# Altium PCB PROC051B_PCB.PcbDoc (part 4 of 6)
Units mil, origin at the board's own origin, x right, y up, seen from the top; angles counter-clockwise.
Board outline 3304.03 x 2647.77 mil, 6 copper layers (TOP, L2, L3, L4, L5, BOTTOM), stack 55.54 mil thick; 356 components, 272 nets, 1247 pads, 1391 vias.

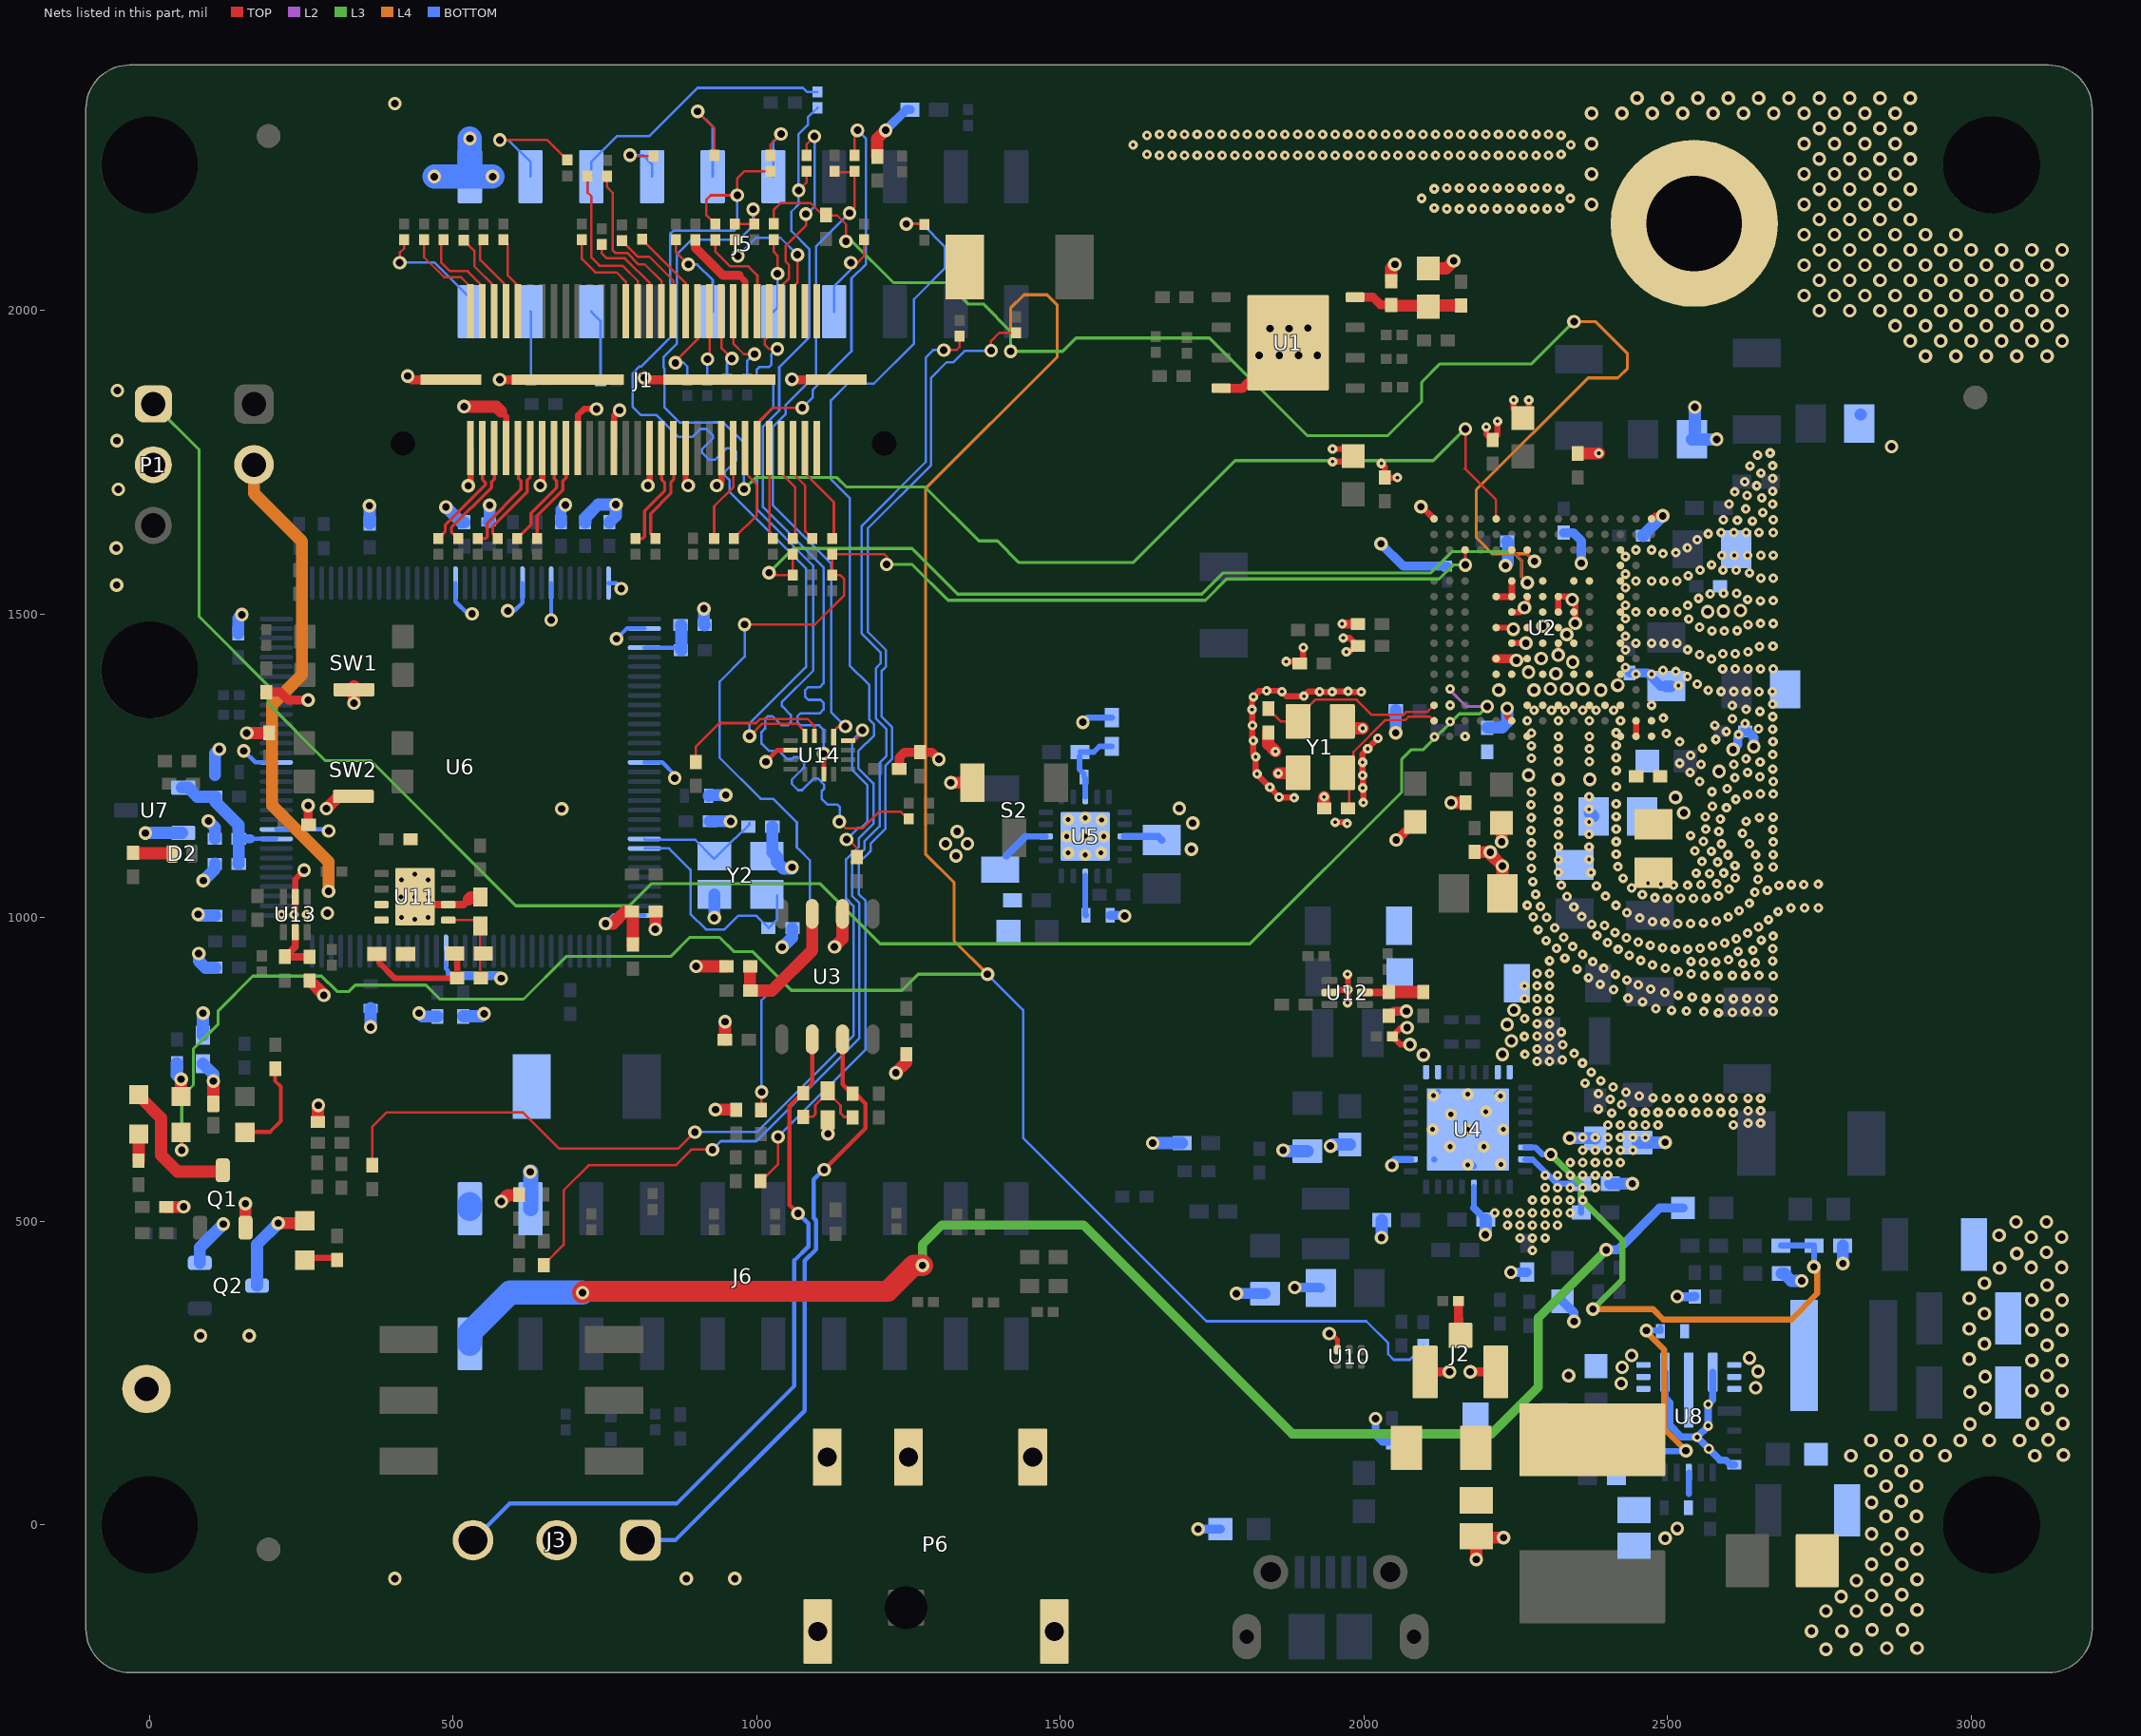
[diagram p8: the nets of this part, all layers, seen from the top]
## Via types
v1: diameter 22.4, hole 12.2, TOP to BOTTOM, tented both sides, 729 vias
v2: diameter 13.77/15.74 (per signal layer), hole 5.9, TOP to L2, tented both sides, 620 vias
v3: diameter 19.68, hole 7.87, TOP to BOTTOM, 25 vias
v4: diameter 22.4, hole 12.1, TOP to BOTTOM, tented both sides, 7 vias
v5: diameter 19.68, hole 7.87, TOP to BOTTOM, tented both sides, 5 vias
v6: diameter 16, hole 8, TOP to BOTTOM, tented both sides, 4 vias
v7: diameter 22.4/22.4/22.4/22.4/22.4/22.4 (per signal layer), hole 12.2, TOP to BOTTOM, tented both sides, 1 vias

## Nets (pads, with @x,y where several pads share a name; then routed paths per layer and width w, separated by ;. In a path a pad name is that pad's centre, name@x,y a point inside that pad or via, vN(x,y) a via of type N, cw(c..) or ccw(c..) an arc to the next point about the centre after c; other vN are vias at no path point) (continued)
AR_TDI: R29.1 R30.1 U2.R11 | length 2240.1
  TOP w4: R29.1@963.83,2142.71 R30.1@995.75,2142.71 995.75,2167 995.75,2168.25 994.5,2167 v1(994,2167) ; v1(2167.14,1804.93) 2167.14,1741.14 2166,1740 2217.78,1688.22 U2.R11@2217.78,1657.03
  L3 w5: v1(979,1706) 998,1725 1132.14,1725 1147.6,1709.54 1277.06,1709.54 1365.9,1620.7 1396.3,1620.7 1432,1585 1619.86,1585 1787.86,1753 2114,1753 2165.93,1804.93 v1(2167.14,1804.93)
  BOTTOM w4: v1(979,1706) 979,1782 945,1816 928.35,1816 927.65,1815.3 873.55,1815.3 848.3,1840.55 848.3,1904.55 846.8,1906.05 846.8,1923.8 868.2,1945.2 868.2,2092.2 893,2117 971.23,2117 994,2139.77 v1(994,2167)
AR_TDO_SOP0: R67.2 R71.1 R89.1 U2.N13 | length 2324.2
  TOP w4: v1(980,1483) 980.2,1482.8 1025.12,1482.8 1025.32,1483 1096,1483 1144,1531 1144,1558 1137.29,1564.71 R71.1@1124.33,1564.71 1124.25,1564.79 R67.2@1124.25,1598.73 1210.27,1598.73 1214,1595 v1(1214,1582) ; R89.1@1006.58,682.45 R89.1@1006.58,683.24 1008,684.66 v1(1008,713) ; U2.N13@2166.6,1605.85 2167,1606.25 2167,1605.85 v1(2167,1581)
  L3 w5: v1(1214,1582) 1256,1582 1315,1523 1739,1523 1774,1558 2124,1558 2147,1581 v1(2167,1581)
  BOTTOM w4: v1(980,1483) 980,1430 938.8,1388.8 938.8,1263.62 1006.42,1196 1027.14,1196 1066,1157.14 1066,1115.86 1069.66,1112.2 1070.09,1112.2 1087.5,1094.8 1087.5,943.5 1008,864 v1(1008,713)
AR_TMS: R65.2 R69.1 U2.N10 | length 1501.2
  TOP w4: v1(1020.36,1568.35) 1024,1564.71 R69.1@1059.25,1564.71 R65.2@1059.25,1598.73 ; U2.N10@2243.37,1605.85 2260,1589.22 2260,1561 v1(2269,1552)
  L3 w5: v1(1020.36,1568.35) 1060.11,1608.1 1255.7,1608.1 1330.8,1533 1733,1533 1768,1568 2110,1568 2145.3,1603.3 2244.56,1603.3 2259.7,1588.16 2259.7,1561.3 v1(2269,1552)
AR_VBGAP: C56.2 U2.B10 | length 82.6
  TOP w10: v1(2236,1345) 2236,1331.73 U2.B10@2243.37,1324.36
  BOTTOM w20: C56.2@2203.69,1313.3 2227.3,1313.3 2236,1322 v1(2236,1345)
AR_VOUT_PA: C10.2 C65.2 C83.2 R137.2 U2.A2 U2.B2 | length 25.6
  TOP w10: U2.A2@2448.09,1298.77 U2.B2@2448.09,1324.36
  other v1: 2526.79,1172.71 2513.12,1198
AR_VSENSE: P1.1 U2.D14 | length 3040.6
  L2 w5: v2@2141.01,1375.54 2168.54,1348 v1(2203,1348)
  L3 w5: P1.1@6.27,1846.15 81.5,1770.92 81.5,1496 195.2,1382.3 195.2,1352.8 289,1259 364,1259 603.2,1019.8 790.3,1019.8 826.7,1056.2 1104,1056.2 1203.2,957 1812.14,957 2062.3,1207.16 2062.3,1261.3 2078,1277 2098,1277 2157,1336 2191,1336 v1(2203,1348)
  other v2: 2142,1377
AR_WARMRST: DS2.2 R15.1 R18.1 R149.2 U2.N9 | length 6560
  TOP w4: DS2.2@52,647.46 DS2.2@52,646.47 52,618 v1(53,617) ; R18.1@1028.21,2143.06 1028.21,2166.22 1038.99,2177 1089.07,2177 1111.26,2154.8 R15.1@1114,2157.53 1114,2156.75 1132.24,2156.75 1147,2141.99 v1(1147,2114) ; U2.N9@2268.96,1605.85 2268.96,1599.04 v1(2281,1587)
  L3 w5: v1(53,617) 53,705.23 72.16,724.39 72.16,784.16 113,825 113,847 170,904 283.26,904 308.65,878.61 328.4,878.61 338.79,889 455,889 478,866 616,866 686.22,936.22 858.1,936.22 889.58,967.7 938.89,967.7 962.29,944.3 992.7,944.3 1056.7,880.3 1239.3,880.3 1266,907 v1(1380,907) ; v1(1147,2114) 1157,2114 1225,2046 1313,2046 1348,2011 1373,2011 1418,1966 v1(1418,1933) 1504,1933 1526,1955 1745.9,1955 1906.9,1794 2039,1794 2095,1850 2095,1881.86 2125.44,1912.3 2276.3,1912.3 v1(2346,1982)
  L4 w5: v1(1380,907) 1325,962 1325,1058 1277.98,1105.02 1277.98,1706.98 1495,1924 1495,2009 1478,2026 1440,2026 1418,2004 v1(1418,1933) ; v1(2281,1587) 2268.3,1599.7 2211.3,1599.7 2185,1626 2185,1705 2369,1889 2418.26,1889 2434.06,1904.81 2434.06,1929.34 2381.7,1981.7 2346,1981.7 2341.7,1981.7 2342,1982 v1(2346,1982)
  BOTTOM w4: v1(1380,907) 1438.7,848.3 1438.7,637.3 1740.61,335.39 2003.85,335.39 2040,299.23 2040,281 2049,272 2075.69,272 R149.2@2098,294.31
AR_XTALM: C9.2 U2.C15 Y1.1 | length 318.1
  TOP w4: C9.2@1842.36,1344.03 1862.93,1323.46 1891.58,1323.46 1892.3,1323.46 1892.3,1331.6 1919.8,1359.1 1987.9,1359.1 2013,1334 2065,1334 2070.2,1339.2 2104.67,1339.2 U2.C15@2115.42,1349.95
AR_XTALP: C15.2 U2.B15 Y1.3 | length 264
  TOP w4: C15.2@1975.7,1180.4 1975.53,1180.57 1975.53,1228.43 1965.14,1238.82 1982.7,1256.38 1982.7,1273.22 2035.48,1326 2068.31,1326 2073.51,1331.2 2108.57,1331.2 U2.B15@2115.42,1324.36
CAN_RX: R12.1 U14.3 | length 260.6
  TOP w4: R12.1@900,1256.68 900,1282 938.59,1320.59 998.85,1320.59 1005.76,1327.5 1083.63,1327.5 1095.13,1316 U14.3@1095.13,1299.5
CAN_TX: R11.1 U14.16 | length 286.9
  TOP w4: v1(1148,1129) 1151,1129 1165,1115 R11.1@1165,1099.68 ; U14.16@1150.24,1291.62 1161.62,1291.62 1174,1304 v1(1174,1309)
  BOTTOM w4: v1(1148,1129) 1166.8,1147.8 1171.8,1147.8 1182.54,1158.54 1182.54,1218.04 1157,1243.58 1157,1292 v1(1174,1309)
CS1: R1.2 R17.1 U14.11 | length 1358.5
  TOP w4: v1(1069,2198) 1082,2211 R17.1@1082,2229.73
  TOP w8: v1(1110,1270) 1110.87,1269.13 U14.11@1110.87,1236.5
  BOTTOM w4: R1.2@1100,2334.01 1084.08,2318.08 1084.08,2305.8 1069,2290.72 v1(1069,2198) 1069,2175 1057,2163 1057,2131 1087,2101 1087,1957 1037,1907 1037,1835.7 1010.3,1809.01 1010.3,1676.7 1110,1577 1110,1386 1104,1380 1085,1380 1080,1375 1080,1364 1085,1359 1105,1359 1110,1354 1110,1343 1104,1337 1072,1337 1067,1332 1067,1322 1072,1317 1103,1317 1110,1310 v1(1110,1270)
D_LOGGER: J5.4 R60.1 | length 214.1
  TOP w4: v1(577,2281) 654.99,2281 R60.1@688,2247.99
  BOTTOM w4: v1(577,2281) 591,2281 627.5,2244.5 J5.4@627.5,2220.72
GND: C1.1 C2.1 C3.1 C4.1 C5.1 C6.1 C7.1 C8.2 C9.1 C10.1 C11.1 C12.1 C13.1 C14.1 C15.1 C16.1 C17.1 C20.1 C21.2 C22.2 C23.2 C24.1 C25.2 C26.2 C27.2 C28.2 C29.2 C30.2 C31.2 C32.2 C33.1 C34.2 C35.2 C36.1 C38.2 C39.1 C41.2 C42.1 C43.1 C44.2 C45.1 C46.2 C47.1 C48.1 C49.1 C50.1 C51.1 C52.1 C53.1 C54.1 C56.1 C57.1 C58.1 C59.2 C60.2 C61.2 C62.2 C63.1 C64.1 C65.1 C66.1 C67.1 C68.2 C69.1 C70.1 C71.1 C73.2 C74.1 C75.1 C76.2 C77.2 C78.2 C79.2 C81.2 C82.2 C83.1 C84.1 C85.2 C86.1 C87.1 C89.1 C90.1 C91.1 C92.1 C93.2 C94.1 C97.1 C98.2 C101.2 C103.2 C104.2 J1.18 J1.24 J1.30 J1.36 J1.42 J1.48 J1.54 J1.60 J1.MP1 J1.MP2 J1.MP3 J1.MP4 J2.2 J2.3 J3.2 J5.2 J6.4 P1.2 P6.2 P6.3 P6.4 P6.5 pad.1 Q1.2 Q2.2 R13.1 R73.1 R79.1 R86.2 R88.1 R96.1 R110.1 R114.1 R118.1 R123.2 R125.1 R126.2 R138.1 R139.1 R145.1 R147.2 R153.1 R158.2 R167.1 R174.1 R175.1 R190.1 R193.1 R208.2 S2.3 SW1.5 SW2.5 TP1.1 U1.4 U1.9 U2.A1 U2.A3 U2.A5 U2.A7 U2.A9 U2.A13 U2.A15 U2.B1 U2.B3 U2.B5 U2.B7 U2.B9 U2.B14 U2.C1 U2.C3 U2.C4 U2.C5 U2.C6 U2.C7 U2.C8 U2.C9 U2.C14 U2.E1 U2.E2 U2.E3 U2.E5 U2.E6 U2.E8 U2.E10 U2.E11 U2.F3 U2.F9 U2.F11 U2.G1 U2.G2 U2.G3 U2.G6 U2.G7 U2.G8 U2.G10 U2.H3 U2.H7 U2.H9 U2.H11 U2.J1 U2.J2 U2.J3 U2.J6 U2.J7 U2.J8 U2.J10 U2.K3 U2.K7 U2.K8 U2.K9 U2.K10 U2.K11 U2.L1 U2.L2 U2.L3 U2.L5 U2.L6 U2.L8 U2.L10 U2.M3 U2.N1 U2.N2 U2.N3 U2.R1 U2.R15 U3.2 U4.4 U4.10 U4.17 U4.18 U4.23 U4.24 U4.33 U5.8 U5.18 U5.21 U6.10 U6.17 U6.48 U6.55 U6.58 U6.64 U6.66 U6.80 U6.114 U7.2 U8.3 U8.5 U8.6 U8.7 U8.8 U8.10 U8.11 U8.12 U8.13 U8.17 U8.20 U10.3 U11.6 U11.9@436.9,1034.5 U12.2 U13.2 U14.6 Y1.2 Y1.4 Y2.2 Y2.4 | length 8165.6
  TOP w7: U2.J7@2318.89,1503.49 U2.J7@2320.14,1503.49 U2.J7@2320.61,1503.49 ; v1@2320.14,1432.71 U2.G7@2320.14,1452.31
  TOP w7.5: v1(1015,1257) 1033.87,1275.87 U14.6@1055.76,1275.87
  TOP w8: v1(1943,315) 1943,318 1944.5,316.5 1956.32,304.68 U10.3@1956.32,288.57
  TOP w9: v1@2268.96,1515.31 U2.K9@2268.96,1529.08
  TOP w10: v2@240,1013 U13.2@240,1034.53 240,1063.8 v1(254.6,1078.4) ; v1(524.98,1711.53) 528.62,1715.17 J1.60@528.62,1773.27 ; 579,1834 587.67,1825.33 587.67,1773.46 J1.54@587.67,1773.27 ; v1(643.53,1711.97) 646.73,1715.17 J1.48@646.73,1773.27 ; J1.42@705.78,1773.27 705.78,1773.46 705.78,1828 715.78,1838 v1(736,1838) ; J1.36@764.84,1773.27 764.84,1773.46 764.84,1826.84 v1(774,1836) ; v1(820.61,1711.89) 823.89,1715.17 J1.30@823.89,1773.27 ; J1.24@882.95,1773.27 882.95,1716.05 v1(887,1712) ; v1(934,1712) 938.83,1712 942,1715.17 J1.18@942,1773.27 ; v2(1872,1422) 1894.32,1422 1895.7,1422 1900,1426.3 v2(1900,1445) ; v2(1885,1197.5) 1885,1198.4 v2(1860.1,1198.4) 1860.1,1199.9 v2(1845,1215) 1824,1236 v2(1824,1237) 1821.6,1239.4 v2(1821.6,1265) 1817.7,1268.9 v2(1817.7,1291.5) 1816.3,1292.9 v2(1816.3,1316.6) 1816.3,1342.3 v2(1815.7,1342.9) 1815.7,1361.7 v2(1818,1364) 1827.9,1373.9 v2(1839.7,1373.9) 1863.6,1373.9 v2(1865,1372.5) 1872.6,1364.9 v2(1901.3,1364.9) 1908.8,1372.4 v2(1927,1372.4) 1927.4,1372 v2(1947.6,1372) 1948.43,1372.83 v2(1974.02,1372.83) 1974.95,1371.9 1995.7,1371.9 v2(1995.8,1372) ; U12.2@1943.37,876.9 1953.7,876.9 1958.3,881.5 v2(1973.69,881.5) ; v2(1948.3,1751.3) 1973,1751.3 C89.1@1982.1,1760.4 1970.4,1772.1 v2(1948.3,1772.1) ; v2(1952.62,1157.3) 1970.3,1157.3 v2(1972.4,1155.2) ; v2(1966,1461) 1976,1461 1989.66,1447.34 1986.31,1444 1982,1444 1976,1438 v2(1971,1438) ; v2(1973,859.98) 1973.69,860.66 v2(1973.69,881.5) ; v2(1973,907) 1973.69,906.31 v2(1973.69,881.5) ; v2(1999.1,1189.7) 1999.1,1212.8 v2(1998.1,1213.8) 1998.1,1234 v2(1997.7,1234.4) v2(1997.7,1256.1) 1997.7,1270 v2(2006.2,1278.5) v2(2023.15,1295.45) ; v2(2028.8,1748.3) 2034.5,1742.6 C6.1@2034.5,1725.28 2034.5,1724.9 v2(2055.3,1724.9) ; v1(2071,819) 2060.99,819 R167.1@2046.59,804.6 2060.19,791 v1(2076,791) ; v1(2094,1677) 2095.45,1677 U2.R15@2115.42,1657.03 ; v2(2201.4,1808.4) 2201.4,1796.9 2211.4,1786.9 2211.95,1786.9 2212.14,1787.09 2219.9,1794.85 v2(2219.9,1817.8) ; U2.H11@2217.78,1477.9 2246,1477.9 2248.55,1477.9 v1(2246,1475.35) v1@2246,1472 ; U2.G10@2243.37,1452.31 v1@2266.94,1452.31 ; U2.J10@2243.37,1503.49 2257.14,1503.49 v1(2264.45,1510.8) ; v2(2246.6,1852.7) 2246.6,1837.55 2261.25,1822.9 C87.1@2261.8,1822.9 2271.5,1832.6 v2(2271.5,1852.5) ; U2.J7@2320.14,1503.49 U2.K7@2320.14,1529.08 2336.12,1529.08 2342.1,1523.1 2348,1517.2 2348,1503.49 v1(2348,1485) ; U2.R1@2473.68,1657.03 2478.65,1662 v1(2492,1662)
  TOP w11: U2.K11@2217.78,1529.08 U2.K10@2243.37,1529.08 U2.L10@2243.37,1554.67
  TOP w12: v5(436.9,1034.5) 449.7,1021.7 459.54,1021.7 U11.6@492.02,1021.7 516.9,1021.7 525.7,1030.5
  TOP w15: R73.1@192.05,1372.02 214.98,1372.02 228.5,1358.5 v1(261,1358.5) ; R79.1@261.15,1153.14 v1(261.15,1185) ; v1(425.2,1892.3) 431.24,1886.26 J1.MP4@496.12,1886.26 J1.MP4@496.73,1886.26 ; v1(576.76,1886.26) J1.MP3@688.64,1886.26 J1.MP3@689.25,1886.26 ; v1(815,1889) 817.74,1886.26 J1.MP2@938.64,1886.26 J1.MP2@939.25,1886.26 ; v1(1058,1887) 1058.74,1886.26 J1.MP1@1131.16,1886.26 J1.MP1@1131.77,1886.26 ; C97.1@1234.68,1245 1235,1245.32 1235,1264 1243.69,1272.69 R208.2@1269,1272.69 1288.31,1272.69 v1(1300,1261) ; U1.4@1762.93,1872.18 U1.4@1764.89,1872.18 1800.13,1872.18 1857.42,1929.47 U1.9@1875.13,1947.18 ; v2(1964,1484) C4.1@1990.32,1484 ; C91.1@2041,838.32 2041.32,838 2049.32,846 v1(2070,846) ; v1(2053,1128) 2054.55,1128 C14.1@2084.45,1157.9 ; J2.2@2100.93,252 v1(2141,252) ; v1(2175,252) J2.3@2217.07,252 ; U2.F11@2217.78,1426.72 2248.28,1426.72 v1(2251,1424)
  TOP w20: R110.1@26.62,523.77 R110.1@27.4,523.77 v1@55,523.77 ; Q1.2@157.98,489.51 v1(158,529) ; v1(160,1304.2) C11.1@197.3,1304.2 ; C92.1@263.6,896.9 263.79,896.71 287.1,873.4 v1(287.1,872.3) ; R114.1@277.32,664 277.32,690.32 v1(278,691) ; v1(291.2,1179.7) 311.4,1199.9 SW2.5@335.7,1199.9 ; v1(336.65,1353.5) SW1.5@336.65,1375.52 SW1.5@336.65,1381.42 ; v1(518,1842) 571,1842 579,1834 ; 525.7,1030.5 529.11,1033.91 R193.1@544.7,1033.94 R193.1@544.9,1033.91 ; v1(579.2,532.5) 589.85,543.15 R96.1@608.78,543.15 ; v1(833,981) 833.3,981.3 C71.1@833.3,1010.5 ; v1(900,920) C16.1@949.91,920 C16.1@950.3,920 ; v1(932,684) 964.87,684 965.73,683.14 R88.1@966.12,682.75 ; C20.1@947.89,798.85 v1(947.89,828.89) ; v1(1117.1,644.1) C24.1@1117.1,667.48 C24.1@1117.1,671.8 ; v1(1128,952) 1141.31,965.31 U3.2@1141.31,1006.33 U3.2@1141.31,1007.31 ; R13.1@1198.4,2252.95 R13.1@1198.4,2253.73 1198.4,2283 v1(1212.4,2297) ; v1(1229,744.5) 1246.3,761.8 R86.2@1246.3,775.01 R86.2@1246.3,775.8 ; v1(1319.72,1222.28) S2.3@1355.1,1222.28 ; C9.1@1842.36,1305.43 C9.1@1842.36,1305.05 1842.36,1285.94 v2(1854.3,1274) ; v2(1859,1238) 1891.48,1238 1891.87,1238.39 Y1.2@1892.3,1238.82 ; C15.1@1934.32,1180.4 v2(1934.32,1198.99) ; Y1.4@1965.14,1323.46 1976.6,1312 v2(1998,1312) ; C2.1@2044.9,2048.2 C2.1@2044.9,2048.59 2044.9,2069.9 v1(2051,2076) ; C1.1@2102,2068.5 C1.1@2104.5,2071 ; C1.1@2106,2069.5 2135.5,2069.5 v1(2148,2082) ; v1(2143.51,1189.51) C12.1@2167.2,1189.51 C12.1@2167.2,1189.9 ; C90.1@2184,1108.32 2207.68,1108.32 v1(2208,1108) 2208,1105 v1(2228,1085) C17.1@2228,1040 ; v1(2185,-57) C79.2@2185,-18.53 2187.47,-21 v1(2230,-21) ; C17.1@2213.1,1028.1 C17.1@2213.1,1037.6 ; C13.1@2226.5,1156.4 2227,1155.9 v1(2227,1125) ; C3.1@2352,1764.68 2386.68,1764.68 v2(2387,1765)
  BOTTOM w7: v1(155,1275) 174.09,1255.91 U6.17@208.64,1255.91 ; U6.10@208.64,1145.68 292.32,1145.68 v1(295,1143) ; U6.114@488.17,944.89 488.17,916.23 491.4,913 491.5,913 491.5,908.5 495.2,904.8 ; U6.48@503.92,1551.19 503.92,1520.59 524.01,1500.5 v1(531,1500.5) ; v1(590,1505.5) 601,1505.5 614.15,1518.65 U6.55@614.15,1551.19 ; v1(661.4,1490.3) U6.58@661.4,1551.19 ; U6.64@755.88,1551.19 769,1551.19 777,1543.19 v1(777,1542) ; v1(769,1459.5) 785.89,1476.39 U6.66@814.94,1476.39 ; U6.80@814.94,1255.91 844.49,1255.91 865,1235.4 v1(865,1230)
  BOTTOM w10: C61.2@106.73,1233.92 106.53,1233.72 106.53,1233.62 106.73,1233.62 106.94,1233.42 108.35,1234.83 108.35,1235 C61.2@107.94,1235.41 ; 1443.04,1134.04 U5.18@1476.04,1134.04 ; v1(1537,1322) 1544.62,1329.62 R145.1@1585,1329.62 ; U4.33@2115.94,602.06 U4.33@2116,602 ; U4.33@2121,712 U4.33@2122.06,713.06 ; U4.33@2175,597 2175.04,596.96 U4.33@2181.11,590.89 ; 2181.11,521.89 U4.4@2181.11,556.78 ; U4.33@2219,710 2219.83,710.83 U4.33@2220.48,711.48 ; 2535,51 U8.20@2535,86.19
  BOTTOM w12: 1411,1102 1443.04,1134.04 ; U5.8@1606,1134 1661,1134 C59.2@1667,1128 ; v1(2019,175) 2019,148 2030.68,136.32 R174.1@2046,136.32 ; v1(2046,592) 2046,597 2051.06,602.06 U4.10@2076.78,602.06 ; 2181.11,521.89 2200,503 C22.2@2200.62,503 ; U8.3@2460.2,155.09 2493.09,155.09 2503.01,165.01 2523.01,145 v6@2548.23,145 ; U8.8@2495.63,251.54 2495.63,209.5 2504,201.13 2504,166 ; U8.10@2574.37,251.54 2574.37,206 v6(2567,198.63) v6(2567,163) v6(2548.62,144.62) v6(2568,125.23) 2586.53,106.7 2596.3,106.7 2604.02,98.98 U8.17@2609.8,98.98
  BOTTOM w15: 495.2,904.8 574.3,904.8 v1(579.1,900) ; v1(1212.4,2297) 1246.4,2331 R147.2@1252.38,2331 ; C73.2@1582,1004 v1@1605,1004 ; v1(1727,-7) R175.1@1763.5,-7 ; v1(1886,391) 1928,391 C93.2@1929,390 ; v1(2028,1616) 2065.01,1578.99 C8.2@2137,1578.99 ; v1(2242,416) 2267.38,416 2268,415.38 R158.2@2269,416.38 ; C94.1@2327,368.5 2346,349.5 v1(2346,335) ; C48.1@2329,1634.32 2344.68,1634.32 2358,1621 v1(2358,1584) ; C51.1@2437.15,1403.22 2466.78,1403.22 2488.6,1381.4 C52.1@2498.15,1381.4 ; v1@2516.32,376.32 v1(2516,376) 2544.68,376 R138.1@2545,376.32 ; v1(2608,1277) 2616,1285 2616,1297 2626,1307 C57.1@2627.68,1307 2632,1307 2642,1297 v1(2642,1282)
  BOTTOM w18: R125.1@677.52,1651.53 677.52,1672.52 v1(685,1680) ; v1(1790,381) C81.2@1837,381
  BOTTOM w20: v1(-7,1139.5) -2,1139.5 -2,1139.69 U7.2@53.36,1139.69 ; v1(80,1005.5) 81.94,1003.56 C69.1@107.96,1003.56 C69.1@108.35,1003.56 ; v1(81,941) 81,929 92.26,917.74 R153.1@107.96,917.74 ; Q2.2@82.76,431.4 82.76,456.76 v1(121.4,495.4) ; R118.1@88,806.62 v1(88,843) ; v1(88.4,1061.1) 107.95,1080.65 C67.1@107.95,1088.8 ; v1(97,1159.5) 107.89,1148.61 C66.1@107.89,1130.1 ; C61.2@107.94,1235.41 107.94,1240.06 107.94,1270.74 v1(114.7,1277.5) ; C50.1@145.95,1468 C50.1@145.95,1468.39 145.95,1493.15 v1(152,1499.2) ; v1(362,1678.5) 362.52,1677.98 C43.1@362.52,1649.53 C43.1@362.52,1649.15 ; v1(364,820) C76.2@364,851 ; v1(444,843) 449.54,837.47 C75.1@473.68,837.47 ; v1(488,1676.5) 513.35,1651.15 C42.1@518.22,1651.15 ; C74.1@516.6,837.85 546.85,837.85 v1(550.9,841.9) ; C41.2@558.3,1651.85 560,1653.55 v1(560,1679.5) ; R125.1@677.52,1650.75 R125.1@677.52,1651.53 ; R126.2@717.68,1651.05 R126.2@717.68,1651.84 717.68,1659.18 739,1680.5 v1(768,1680.5) 768,1661.77 757.67,1651.44 R123.2@757.28,1651.05 ; v1(913,1509) 913,1482.93 C49.1@914.04,1481.9 ; C62.2@921,1201 922,1202 v1(949,1202) ; C64.1@922.68,1159 955.5,1159 956,1158.5 v1(957,1158.5) ; v1(930,1000) 930.15,1000.15 Y2.4@930.15,1038.54 ; C63.1@1025.68,1150 1025.68,1107.86 1033.27,1100.28 1033.27,1091.73 1043.67,1081.33 1058,1081.33 v1(1058,1083) ; v1(1041.8,951.5) 1041.8,950.8 1042.15,951.15 1058.68,967.68 C70.1@1058.68,983 ; v1@1605,1004 v1(1606,1003) ; v1(1652,629) R190.1@1700.38,629 ; v1(1867,617) 1868.37,615.63 C35.2@1907,615.63 ; v1(1945,624) 1947.5,626.5 C36.1@1977,626.5 ; v1(2029,473) 2029.38,473.38 C82.2@2029.38,502 ; v1(2052.32,1304.68) C53.1@2052.32,1342 ; v1(2200,478) 2200.62,478.62 C22.2@2200.62,503 ; v1(2233,1580) 2237,1584 2237,1618.68 C7.1@2235.68,1620 ; v1(2339,637) 2380.5,637 C54.1@2381,636.5 ; C65.1@2372,1173 C65.1@2378,1167 ; C77.2@2405.62,562 v1(2442,562) ; C46.2@2451,629.63 2495.63,629.63 v1(2496,630) ; C39.1@2460,1628.68 C39.1@2459.68,1629 2459.68,1629.68 v1(2492,1662) ; C52.1@2498.15,1381.4 C52.1@2505.4,1381.4 ; v1(2545,1841) 2545,1793 C98.2@2540,1788 v1(2581,1788) ; R139.1@2687.62,414 2692,414 2704,402 v1(2721,402) ; v1(2788.62,430.38) C78.2@2788.62,460
  BOTTOM w25: v1(627,581.5) 627.5,581.5 J6.4@627.5,520.72
  BOTTOM w40: v1(469,2220.72) J5.2@527.5,2220.72 ; v1(527.5,2283.5) J5.2@527.5,2220.72 ; v1(565,2220.72) J5.2@527.5,2220.72
  other v1: 2761,-205 2811,-205 2861,-203 2911,-203 2737,-175 2787,-175 2837,-173 2887,-173 2761,-142 2811,-142 2861,-140 2911,-140 2786,-118 2836,-116 2886,-115 2811,-92 2861,-90 2911,-90 404,-88.5 884,-88.5 964,-88.5 2836,-65 2886,-65 2861,-40 2911,-40 2496,-22 2836,-15 2886,-15 2516,-6 2860,14 2910,14 2836,37 2885,39 2860,64 2910,64 2835,89 2885,89 2802,114 2860,114 2910,114 2957,114 3105,114 3152,115 2835,139 2885,139 2932,139 2982,139 3030,139 3080,139 3127,140 2998,166 3101,167 3151,167 3023,192 3126,192 2998,219 3100,221 3150,221 2645,226 2423.67,232.91 3023,244 2337,246 3125,246 2649,253 2425.13,259.59 3100,271 3150,271 2997,273 2635,275 2441,279 3125,296 3022,298 84,311.5 164,311.5 3100,321 3150,321 2997,323 3125,346 3022,348 3100,370 3150,370 2997,373 3125,395 3022,398 3047,423 3099,424 3149,424 3075,447 3124,449 3099,474 3149,474 3046,477 3074,499 3124,499 56,524 2098,774 2228,775 2243,797 2236,824 2247,848 1328,1102 1716,1113 1311,1122 1347,1122 1330,1142 1718,1156 678.8,1179.5 1696,1180 2320,1228 2372,1228 2585,1241 2222,1375 2280,1375 2390,1375 2307,1377 2334,1377 2360.75,1376.8 2418,1383 2316,1402 2271.2,1404.5 2344,1421 2292,1427 2320.15,1432.7 2266.95,1452.3 2334,1466.51 2295.05,1480.4 2566,1504 2592,1505 2620,1506 2343,1524 -54.3,1547.9 -54.8,1609.1 -51.5,1705.6 2869,1776 -53.7,1785.9 -52.9,1868.3 2925,1925 2975,1925 3025,1925 3075,1925 3125,1925 2900,1950 2950,1950 3000,1950 3050,1950 3100,1950 3150,1950 2875,1975 2925,1975 2975,1975 3025,1975 3075,1975 3125,1975 2750,2000 2800,2000 2850,2000 2900,2000 2950,2000 3000,2000 3050,2000 3100,2000 3150,2000 2725,2025 2775,2025 2825,2025 2875,2025 2925,2025 2975,2025 3025,2025 3075,2025 3125,2025 2750,2050 2800,2050 2850,2050 2900,2050 2950,2050 3000,2050 3050,2050 3100,2050 3150,2050 2725,2075 2775,2075 2825,2075 2875,2075 2925,2075 2975,2075 3025,2075 3075,2075 3125,2075 2750,2100 2800,2100 2850,2100 2900,2100 2950,2100 3000,2100 3050,2100 3100,2100 3150,2100 2725,2125 2775,2125 2825,2125 2875,2125 2925,2125 2975,2125 2750,2150 2800,2150 2850,2150 2900,2150 2375,2175 2725,2175 2775,2175 2825,2175 2875,2175 2750,2200 2800,2200 2850,2200 2900,2200 2375,2225 2725,2225 2775,2225 2825,2225 2875,2225 2750,2250 2800,2250 2850,2250 2900,2250 2375,2275 2725,2275 2775,2275 2825,2275 2875,2275 2750,2300 2800,2300 2850,2300 2900,2300 2375,2325 2425,2325 2475,2325 2525,2325 2575,2325 2625,2325 2675,2325 2725,2325 2775,2325 2825,2325 2875,2325 404,2341 2450,2350 2500,2350 2550,2350 2600,2350 2650,2350 2700,2350 2750,2350 2800,2350 2850,2350 2900,2350
  other v2: 2277.67,451.94 2257,472.61 2277.67,472.61 2298.34,472.61 2236.33,493.28 2257,493.28 2277.67,493.28 2298.34,493.28 2319.01,493.28 2215.66,513.95 2236.33,513.95 2257,513.95 2277.67,513.95 2298.34,513.95 2319.01,513.95 2339.68,513.95 2277.67,534.62 2298.34,534.62 2319.01,534.62 2339.68,534.62 2360.35,534.62 2298.34,555.29 2319.01,555.29 2339.68,555.29 2360.35,555.29 2381.02,555.29 2298.34,575.96 2319.01,575.96 2339.68,575.96 2360.35,575.96 2381.02,575.96 2401.69,575.96 2339.68,596.63 2360.35,596.63 2381.02,596.63 2401.69,596.63 2422.36,596.63 2360.35,617.3 2381.02,617.3 2401.69,617.3 2422.36,617.3 2443.03,617.3 2360.35,637.97 2381.02,637.97 2401.69,637.97 2422.36,637.97 2443.03,637.97 2463.7,637.97 2401.69,658.64 2422.36,658.64 2443.03,658.64 2463.7,658.64 2484.37,658.64 2608.39,658.64 2632.71,661.46 2653.38,661.46 2408.3,678.5 2443.03,679.31 2463.7,679.31 2484.37,679.31 2505.04,679.31 2525.71,679.31 2546.38,679.31 2567.05,679.31 2587.72,679.31 2608.39,679.31 2632.71,682.13 2653.38,682.13 2386.2,684.8 2424.4,692.2 2405.5,701.1 2498.2,702.5 2520.1,702.1 2542.3,702.5 2586.1,702.3 2607.7,702.3 2565.2,703.1 2632.71,702.73 2653.38,702.73 2476.1,703.5 2453.5,706.5 2386.4,710.1 2431.4,712.5 2410.2,721.4 2364.4,727.8 2390.1,731.7 2374.4,745.8 2359.9,760.7 2285.1,763.4 2305.8,763.4 2326.5,765.7 2265.1,774.9 2346.1,776.5 2285.1,784.1 2305.8,784.1 2327.3,790.7 2264.3,804.5 2285.1,804.8 2305.8,804.8 2325.3,811.6 2285.1,825.5 2305.8,825.5 2264.5,833.8 2583.7,843.5 2607,843.9 2560,845.4 2285.1,846.2 2305.8,846.2 2531.2,846.2 2627.6,845.6 2648.2,845.6 2673.8,845.6 2506.5,847.4 2481,850.5 2459,861.5 2608.6,866.4 2630.6,866.5 2264.4,866.9 2285.1,866.9 2305.8,866.9 2563.5,867.1 2586.4,866.6 2652.2,866.6 2674.1,866.9 2435,867.5 2540.7,869 2517.6,872.5 2495.5,876.9 2411,881.5 2472,882.5 2264.4,887.6 2285.1,887.6 2305.8,887.6 2389,890.5 2452,889.5 2433,897.5 2370,901.5 2673.9,904.5 2561.2,905.1 2583.6,904.7 2607.1,904.7 2628.8,904.7 2650.8,904.8 2414,906.5 2538.7,907.4 2285.1,908.3 2305.8,908.3 2517.9,911.5 2351,915.5 2395,916.5 2496.6,916.7 2475.1,922.5 2623.8,924.7 2644.4,926.2 2559,926.8 2579.6,927.3 2377,927.5 2538.4,928 2673,928.5 2305.8,929 2455.7,929.7 2600.4,930.7 2331,933.5 2436.9,938.3 2360,939.5 2616,944.5 2640.7,946.8 2418.6,947.8 2512.5,948.1 2533.1,947.9 2673.5,949.1 2317,949.5 2492,950.5 2553.7,949.6 2344,952.5 2574,953.3 2471.7,954.3 2594,958.3 2401.3,959.1 2451.8,959.9 2300,962.5 2654.2,963.3 2613.3,965.5 2432.4,967.1 2329,967.5 2384.1,970.5 2673.8,969.7 2631.9,974.5 2413.7,975.8 2287,980.5 2314,983.5 2649.7,984.9 2396.4,987.1 2375.1,989.1 2517,990.5 2538,990.5 2496,992.5 2559,991.5 2475,993.5 2580,994.5 2666.5,996.9 2301,1000.5 2454,999.5 2279,1001.5 2358.8,1001.8 2600,1001.5 217.33,1005.44 238,1005.44 258.67,1005.44 2433,1008.5 2682.2,1010.3 2618,1011.5 2703.3,1016.4 2725.8,1016.4 2748.6,1016.3 2291,1018.5 2345.8,1017.8 2269,1020.5 2415,1020.5 2634.7,1023.7 2500,1032 2521.5,1032 2542.5,1032 2563.5,1032 2479,1033 2334.5,1035.1 2398,1035.5 2584,1035.5 2283,1038.5 2458.5,1038 2643.9,1042.2 2664.3,1045.3 2601,1047.5 2441,1049 2383,1052.5 2683.3,1053.3 2325,1053.5 2510,1053.5 2533,1053.5 2555,1054.5 2703.9,1054.2 2724.5,1054.5 2748.1,1055 2489,1055.5 2580.9,1055.9 2468,1057 2278,1059.5 2649,1063.2 2427,1065 2611.5,1065.5 2569.1,1072.9 2374,1074.5 2547,1073.6 2592.5,1073.7 2320.1,1074.8 2275.6,1081.3 2673.9,1083.4 2418,1084 2649.8,1083.8 2611.1,1086.1 2582.4,1091.7 2556.9,1092.6 2320.1,1095.5 2370.9,1095.9 2275.7,1102.1 2415.5,1104.5 2599.5,1103.5 2644.9,1103.9 2673.8,1104.1 2545,1110 2572.1,1109.6 2320.1,1116.2 2370.9,1116.6 2589,1121.5 2634.9,1121.9 2275.6,1123.1 2415.5,1125.35 2674,1124.7 2559.1,1125.6 2538,1135.5 2320.1,1136.9 2370.9,1137.3 2623.5,1139.1 2584.5,1142 2275.3,1143.7 2673.6,1145.3 2415.5,1146.05 2563,1145.9 2320.1,1157.6 2370.9,1158 2629.3,1158.9 2587,1162.5 2275.5,1165 2651.2,1165.2 2562,1166.5 2674,1165.9 2415.5,1166.75 2320.1,1178.3 2370.9,1178.7 2597,1181 2574,1183.5 2275.3,1185.9 2415.5,1187.4 2612.5,1195 2320.1,1199 2370.9,1199.4 2632,1202.5 2653,1204 2674.1,1203.8 2275.7,1207 2573,1207.5 2598,1212.5 2415.7,1216.1 2553,1224.5 2674.1,1224.4 2611,1230.5 2652.1,1232.3 2537,1239.5 2632,1239.5 2415.45,1242.6 2673.5,1245 2555,1252.5 2609,1252.5 2520,1254.5 2652.6,1256.3 2320.14,1257.37 2371.32,1257.37 2629.2,1261.9 2275.85,1262.7 2415.45,1263.3 2538,1267.5 2673.5,1268.7 2320.14,1278.07 2371.32,1278.07 2557.2,1279.4 2275.85,1283.35 2415.45,1283.95 2519.9,1289.8 2673.7,1290 2579.7,1293.6 2116,1298 2166.6,1298.5 2320.14,1298.77 2371.32,1298.77 2617,1301.5 2275.85,1304 2498,1303.5 2415.45,1304.6 2596.9,1306.8 2649.7,1311.1 2673,1310.6 2577.7,1317 2627.7,1319.9 2142,1323 2268.96,1324.36 2320.14,1324.36 2371.32,1324.36 2422.5,1324.36 2607,1327.5 2493,1329 2673.2,1331.2 2652.1,1339.8 2280.15,1341.9 2309.05,1341.9 2331.35,1341.9 2360.25,1341.9 2382.55,1341.9 2411.45,1341.9 2629.3,1343 2142,1350 2473.68,1349.95 2606.5,1349.6 2673,1351.8 2650.7,1372.28 2672.8,1372.48 2588.3,1372.68 2609,1372.68 2629.7,1372.68 2567.2,1374.48 2518,1382.5 2549,1384.8 2532.7,1397.48 2448.09,1401.13 2473.68,1401.13 2513.5,1405.68 2492.4,1407.28 2590.8,1410 2611.7,1409.9 2632.5,1409.9 2653.2,1410 2674.1,1409.9 2430.65,1412.3 2572.4,1426 2553,1433.5 2591.1,1434.8 2611.7,1434.8 2632.6,1437.9 2430.65,1441.3 2533,1441.5 2651.5,1446.9 2673.7,1447.3 2448.09,1452.31 2473.68,1452.31 2494.38,1452.31 2515.08,1452.31 2430.65,1463.5 2593.7,1472.2 2573,1472.7 2614.5,1472.8 2552.8,1478.9 2632.8,1482.4 2653.3,1484.7 2674.1,1484.6 2430.65,1492.5 2535.1,1492.1 2448.09,1503.49 2473.68,1503.49 2494.38,1503.49 2515.08,1503.49 2533.2,1514.4 2430.65,1514.7 2652.9,1522 2673.9,1522.2 2632.1,1524.3 2550.9,1526 2570.3,1533.6 2592.3,1534.3 2613.8,1534.1 2430.65,1543.7 2448.09,1554.67 2473.68,1554.67 2494.38,1554.67 2515.08,1554.67 2653.6,1559.4 2674.2,1559.4 2534,1563.5 2430.65,1565.9 2634.9,1568.2 2613.2,1572.5 2553.5,1572.6 2591.4,1572.6 2572.6,1581.5 2430.65,1594.9 2589.3,1596.8 2609.9,1596.8 2631.8,1596.7 2653.6,1596.8 2674.2,1597.1 2492.4,1599.7 2513.5,1601.3 2448.09,1605.85 2473.68,1605.85 2532.7,1609.5 2549,1622.5 2567.2,1632.5 2588.3,1634.3 2609,1634.3 2629.7,1634.3 2674,1634.5 2650.7,1634.7 2615,1654.5 2640,1653.5 2592,1655.5 2674,1655.5 2657,1667.5 2629,1673.5 2601.2,1681.5 2673,1681.5 2655,1691.5 2631,1695.5 2610.7,1701.5 2673,1702.5 2647,1711.5 2627,1718.2 2673,1723.5 2654,1732.5 2635.9,1744.2 2673,1744.5 2648.4,1761.9 2669,1765.5 2136.47,2167.74 2157.14,2167.74 2177.81,2167.74 2198.48,2167.74 2219.15,2167.74 2239.82,2167.74 2260.49,2167.74 2281.16,2167.74 2301.83,2167.74 2115.8,2169.2 2322.5,2169.2 2095.07,2184.9 2339.8,2184.9 2115.8,2200.6 2322.5,2200.6 2136.47,2202.06 2157.14,2202.06 2177.81,2202.06 2198.48,2202.06 2219.15,2202.06 2239.82,2202.06 2260.49,2202.06 2281.16,2202.06 2301.83,2202.06 1663.3,2255.84 1683.97,2255.84 1704.64,2255.84 1725.31,2255.84 1745.98,2255.84 1766.65,2255.84 1787.32,2255.84 1807.99,2255.84 1828.66,2255.84 1849.33,2255.84 1870,2255.84 1890.67,2255.84 1911.34,2255.84 1932.01,2255.84 1952.68,2255.84 1973.35,2255.84 1994.02,2255.84 2014.69,2255.84 2035.36,2255.84 2056.03,2255.84 2076.7,2255.84 2097.37,2255.84 2118.04,2255.84 2138.71,2255.84 2159.38,2255.84 2180.05,2255.84 2200.72,2255.84 2221.39,2255.84 2242.06,2255.84 2262.73,2255.84 2283.4,2255.84 2304.07,2255.84 1642.63,2257.3 2324.69,2257.3 1619.7,2273 2340.6,2273 1642.63,2288.7 2324.69,2288.7 1663.3,2290.16 1683.97,2290.16 1704.64,2290.16 1725.31,2290.16 1745.98,2290.16 1766.65,2290.16 1787.32,2290.16 1807.99,2290.16 1828.66,2290.16 1849.33,2290.16 1870,2290.16 1890.67,2290.16 1911.34,2290.16 1932.01,2290.16 1952.68,2290.16 1973.35,2290.16 1994.02,2290.16 2014.69,2290.16 2035.36,2290.16 2056.03,2290.16 2076.7,2290.16 2097.37,2290.16 2118.04,2290.16 2138.71,2290.16 2159.38,2290.16 2180.05,2290.16 2200.72,2290.16 2221.39,2290.16 2242.06,2290.16 2262.73,2290.16 2283.4,2290.16 2304.07,2290.16
  other v3: 2171.27,593.2 2225.49,594 2141.61,623 2197.39,623 2113.2,651.27 2171.27,651.27 2229.34,651.27 2143.17,676.22 2201,680.8 2224.67,706 2114.5,707 2171.27,709.34 436.9,997.1 414.26,1034.5 459.54,1034.5 436.9,1071.9 1541.04,1103.49 1513,1107 1567,1107 1510.53,1134 1541,1134.04 1571.55,1134 1568,1161 1513,1162 1541.04,1164.51
  other v4: 1827.46,1926.43 1860.46,1926.43 1892.46,1926.43 1923.46,1926.43 1845.46,1970.43 1876.66,1970.48 1907.46,1971.43
  other v5: 414.9,1000.5 458.9,1000.5 414.9,1062.5 458.9,1062.5
  other v7: 2271,1235
MCU_3V3: J6.1 R130.1 | length 2473.3
  TOP w35: v1(713,382.5) 715.2,384.7 1215.7,384.7 1258.5,427.5 v1(1273,427.5)
  L3 w15: v1(1273,427.5) 1273,462 1305,494 1538,494 1882,150 2210,150 2287.3,227.3 2287.3,341.3 v1(2399,453)
  BOTTOM w15: v1(2399,453) 2418,453 2487,522 R130.1@2525.5,522
  BOTTOM w40: J6.1@527.5,298.28 527.5,316.5 593.5,382.5 v1(713,382.5)
MCU_5V: J6.2 R115.1 | length 7.8
  BOTTOM w40: J6.2@527.5,520.72 J6.2@527.5,528.5
MCU_SOP0: R36.1 R93.2 | length 1668.9
  TOP w4: R93.2@1005.82,566.95 1008.14,566.95 1035,593.81 v1(1035,639) ; v1(1386,1934) 1386,1950 1399.73,1963.73 R36.1@1427.25,1963.73
  BOTTOM w4: v1(1035,639) 1179.2,783.2 1179.2,1027.91 1168,1039.11 1168,1090.61 1186.2,1108.81 1188,1110.56 1188,1122.42 1212.2,1146.62 1212.2,1250.91 1223.2,1261.91 1223.2,1313.83 1206,1331.03 1206,1406.7 1212.96,1413.67 1212.96,1440.77 1183,1470.74 1183,1641.55 1287.2,1745.75 1287.2,1889.32 1312.89,1915 1324,1915 1343,1934 v1(1386,1934)
MCU_SOP1: R35.1 R112.2 | length 2023.8
  TOP w4: R112.2@649.32,428.65 682,461.33 682,551 723.2,592.2 866.2,592.2 892,618 v1(927,618) ; v1(1308,1935) 1329,1935 1334,1940 R35.1@1334,1958.01
  BOTTOM w4: v1(927,618) 941,632 999.28,632 1169.2,801.92 1169.2,1023.77 1157.17,1035.8 1157.17,1092.55 1177.2,1112.58 1177.2,1125.76 1202.2,1150.76 1202.2,1255.05 1213.2,1266.05 1213.2,1311.1 1196,1328.3 1196,1410.85 1203.96,1418.81 1203.96,1437.05 1173,1468.01 1173,1645.4 1278.2,1750.6 1278.2,1922.74 1290.46,1935 v1(1308,1935)
MCU_SOP2: R32.1 R101.2 | length 2554.1
  TOP w4: R101.2@366.98,592.54 366.98,655.98 390,679 615,679 674,620 871,620 v1(898,647) ; v1(1246.21,2142.71) 1276,2142.71 R32.1@1277.55,2142.71
  BOTTOM w4: v1(898,647) 1000.14,647 1159.2,806.06 1159.2,1019.63 1147.17,1031.66 1147.17,1096.02 1168.2,1117.05 1168.2,1130.91 1192.2,1154.91 1192.2,1221.4 1167,1246.6 1167,1274.15 1193.2,1300.35 1193.2,1318.38 1185,1326.58 1185,1383.81 1153.2,1415.61 1153.2,1443.66 1153,1443.86 1153,1691.26 1122,1722.26 1122,1852.19 1149.58,1879.77 1192.93,1879.77 1259,1945.85 1259,2019 1310,2070 1310,2105 1272.29,2142.71 v1(1246.21,2142.71)
MISO1: R6.2 R7.2 U14.1 | length 1094.8
  TOP w4: R6.2@1124.05,2227.73 1128.05,2227.73 R7.2@1161.25,2227.73 ; U14.1@1126.62,1297.53 1126.62,1307.62 1134,1315 v1(1146,1315) 1146,1317 v1@1149,1320 ; v1@1152.82,2161.82 1161.25,2170.25 R7.2@1161.25,2227.73 ; R7.2@1161.25,2229.73 R7.2@1161.25,2227.73
  BOTTOM w4: v1(1146,1315) 1123,1338 1123,1583 1026.8,1679.2 1026.8,1808.8 1047.8,1829.8 1047.8,1844.8 1098,1895 1098,2106 v1(1152.82,2160.82)
MOSI1: R4.2 R28.1 U14.4 | length 1619.9
  TOP w4: R28.1@931.5,2142.39 917,2156.89 917,2183 924,2190 v1(968,2190) 968,2218 979.73,2229.73 R4.2@1022.55,2229.73 ; v1(988,1299) 988.58,1299 1009.08,1319.5 1066.5,1319.5 1079.38,1306.62 U14.4@1079.38,1299.5
  BOTTOM w4: v1(968,2190) 968,2137 963,2132 863,2132 857.3,2126.3 857.3,1955.58 809.92,1908.2 807.05,1908.2 795.8,1896.95 795.8,1841.2 809,1828 835,1828 871,1792 894,1792 907,1805 917,1805 928,1794 928,1790 910,1772 910,1765.54 921,1754.54 931.46,1754.54 949.92,1773 961,1773 966,1768 966,1753.08 947.46,1734.54 947.46,1728.08 955.39,1720.15 955.39,1701.17 1081,1575.56 1081,1413 988,1320 v1(988,1299)
NetC1_2: C1.2 C2.2 R37.2 U1.8 | length 168.2
  TOP w15: U1.8@1987.33,2022.18 2014.82,2022.18 2027.4,2009.6 C2.2@2044.9,2009.6
  TOP w20: C2.2@2044.9,2009.6 2045.09,2009.41 2046.4,2008.1 2096.6,2008.1 2097,2008.5 2106,2008.5 2149.5,2008.5
NetC16_2: C16.2 R78.1 U3.3 | length 230.9
  TOP w20: C16.2@988.9,920 988.9,880 R78.1@989.68,880 1025,880 1091.31,946.31 U3.3@1091.31,1006.33 U3.3@1091.31,1007.31
NetC18_1: C18.1 U8.2 | length 324.7
  L4 w10: v1(2465.17,320.28) 2465.17,317.58 2494.36,288.39 2494.36,158.26 v1(2530.31,122.31)
  BOTTOM w10: U8.2@2460.2,121.62 2529.62,121.62 v1(2530.31,122.31) ; v1(2465.17,320.28) 2486.72,320.28 C18.1@2488,319 C18.1@2488,325
NetC18_2: C18.2 L1.1 U8.9
NetC24_2: C24.2 R85.1 R87.2 | length 129.4
  TOP w4: R87.2@1076.7,672.5 1092.6,672.5 1096.5,676.4 1096.5,691.4 1115.5,710.4 1117.1,710.4 1118.7,710.4 1138,691.1 1138,678 1144.1,671.9 R85.1@1158,671.9
NetC32_1: C32.1 R84.2 U8.1
NetC49_2: C49.2 R134.1 U6.68 | length 104.2
  BOTTOM w7: U6.68@814.94,1444.89 871.46,1444.89 875.36,1440.99 R134.1@875.75,1440.6
  BOTTOM w20: C49.2@875.05,1481.9 875.75,1481.2 R134.1@875.75,1440.6
NetC63_2: C63.2 U6.88 Y2.1 | length 212.2
  BOTTOM w4: U6.88@814.94,1129.93 816.37,1128.5 898.5,1128.5 927.81,1099.19 930,1097 932.34,1099.34 964,1131 965,1131 985.16,1151.16 987.7,1153.7 C63.2@987.7,1156
NetC66_2: C66.2 C67.2 R140.1 U6.9 U7.1 | length 249.9
  BOTTOM w7: 166.67,1129.93 U6.9@208.64,1129.93
  BOTTOM w15: C66.2@146.88,1130.1 166.5,1130.1 166.67,1129.93
  BOTTOM w20: U7.1@53.36,1214.49 U7.1@55.32,1214.49 63.44,1214.49 78.41,1199.52 R140.1@107.96,1199.52 108.75,1199.52 108.75,1190.38 146.49,1152.64 C66.2@146.88,1130.1 146.88,1089.13 146.74,1088.99 C67.2@146.55,1088.8
NetC70_2: C70.2 U6.89 Y2.3 | length 380.3
  BOTTOM w4: U6.89@814.94,1114.18 855.82,1114.18 891,1079 891,1006 916.2,980.8 946.8,980.8 969.2,1003.2 999.5,1003.2 1019.51,983.19 1019.7,983 1033.27,996.57 Y2.3@1033.27,1037.28
NetC71_2: C71.2 R154.1 U6.96 | length 174.6
  TOP w20: v1(751,990.5) 763.64,990.5 783.64,1010.5 C71.2@794.31,1010.5 C71.2@794.7,1010.5 ; R154.1@796,955.68 C71.2@796,1008.81
  BOTTOM w7: v1(751,990.5) 764.45,1003.95 U6.96@814.94,1003.95
NetC72_2: C72.2 R122.1 R145.2 U5.3 | length 127.1
  BOTTOM w9: R122.1@1531.62,1266 1531.62,1244.38 1539,1237 C72.2@1539,1232 1541,1230 U5.3@1541.04,1198.96 ; R122.1@1532.62,1273 1555,1273 1564.38,1282.38 R145.2@1585,1282.38
NetC73_1: C73.1 U5.13 | length 65.5
  BOTTOM w10: U5.13@1541.04,1069.04 1541,1005 C73.1@1542,1004
NetC77_1: C77.1 R150.1 U4.31 | length 157.2
  BOTTOM w10: U4.31@2265.76,602.06 2277.94,602.06 2318,562 C77.1@2358.38,562 2357.7,561.32 R150.1@2357.7,514.32
NetC78_1: C78.1 R157.1 U4.30 | length 901.1
  L3 w10: v1(2308,610) 2357.7,560.3 2357.7,536.6 2425.42,468.88 2425.42,403.68 v1(2377,355.26)
  L4 w10: v1(2377,355.26) 2476.1,355.26 2492.97,338.39 2704,338.39 2746.71,381.1 2746.71,419.29 v1(2741,425)
  BOTTOM w10: U4.30@2265.76,621.74 2282.26,621.74 2294,610 v1(2308,610) ; R157.1@2686.62,460 C78.1@2741.38,460 2741.38,425.38 v1(2741,425)
NetC79_1: C79.1 F1.1 L7.1
NetC85_1: C85.1 C88.1 P7.2 R61.2 U11.3 U11.4 | length 973.8
  TOP w10: 378.6,925.6 403.8,900.4 C88.1@506.32,900.4 506.7,900.4 506.9,900.6 R61.2@506.9,941.1
  L4 w20: P7.2@171.94,1746.15 171.94,1699.06 251,1620 251,1400 201.6,1350.6 201.6,1185.4 294.9,1092.1 v1(294.9,1043.5)
  other v1: 292.9,1007.5
NetC88_2: C88.2 R61.1 R193.2 U11.5 | length 145
  TOP w4: U11.5@495.96,996.11 544.7,996.11 544.9,996.11 544.7,995.91 R193.2@544.7,986.7 544.7,941.1 544.7,901 C88.2@545.3,900.4
NetC91_2: C91.2 R196.1 U12.5 | length 88.8
  TOP w12: U12.5@2001.63,876.9 2040.22,876.9 C91.2@2041,877.69
  TOP w20: C91.2@2041,877.69 2089.63,877.69 R196.1@2090,877.32
NetC92_2: C92.2 R200.1 U13.5 | length 88.8
  TOP w12: R200.1@222.7,935.2 R200.1@223,935.5 ; U13.5@240,976.27 240,952.5 223.09,935.59 R200.1@223,935.5 ; C92.2@263.6,935.5 R200.1@223,935.5
NetD2_1: D2.1@37.49,1105.47 R80.2 | length 67.8
  TOP w10: D2.1@36.3,1106.06 36.89,1105.47 D2.1@37.49,1105.47 D2.1@40.34,1105.47
  TOP w20: R80.2@-27.25,1106.06 D2.1@36.3,1106.06
NetD5_2: D5.2 R118.2 | length 72.7
  TOP w20: D5.2@105,693.72 v1(105,731)
  BOTTOM w20: R118.2@88,759.38 105,742.38 v1(105,731)
NetDS1_1: DS1.1 R90.1 | length 156.3
  TOP w6: 198.59,647.59 216,665 216,722 207,731 R90.1@207,751.32
  TOP w7: DS1.1@157,647.59 198.59,647.59
NetDS2_1: DS2.1 R202.1 | length 58.7
  TOP w20: DS2.1@52,704.54 DS2.1@52,705.53 v1(52,734)
  BOTTOM w20: R202.1@45,760.32 45,741 v1(52,734)
NetDS3_1: DS3.1 R103.1 | length 47.8
  TOP w20: R103.1@-18,599.68 DS3.1@-18,643.52 DS3.1@-18,647.46
NetDS3_2: DS3.2 Q1.3 | length 225.1
  TOP w20: DS3.2@-18,704.54 -15.54,704.54 19,670 19,609 45.97,582.03 Q1.3@120.58,582.03
NetDS4_1: DS4.1 R117.1 | length 54.4
  TOP w10: DS4.1@255.6,439.92 305.16,439.92 R117.1@308.61,436.47
NetDS4_2: DS4.2 Q2.3 | length 161
  TOP w20: v1(212,497) DS4.2@255.6,497
  BOTTOM w20: Q2.3@177.24,394 177.24,462.24 v1(212,497)
NetF1_2: F1.2 P6.1
NetJ1_1: J1.1 J1.2 J1.3 R34.1
NetJ1_4: J1.4 R67.1 | length 169.2
  TOP w4: J1.4@1079.8,1773.27 1079.8,1731.4 1127,1684.2 1127,1627.46 R67.1@1124.25,1624.71
NetJ1_5: J1.5 R29.2 | length 246.5
  TOP w4: R29.2@963.83,2116.73 963.83,2095.17 v1(969,2090) ; J1.5@1060.11,1999.25 1060.11,2039.11 1066.9,2045.9 1066.9,2046.64 1067,2046.74 v1(1067,2092)
  BOTTOM w4: v1(969,2090) 999,2120 1039,2120 v1(1067,2092)
NetJ1_6: J1.6 R66.1 | length 161.7
  TOP w4: J1.6@1060.11,1773.27 1060.11,1731.4 1080,1711.51 1080,1636.46 R66.1@1091.75,1624.71
NetJ1_7: J1.7 R17.2 | length 355.3
  TOP w4: J1.7@1040.43,1999.25 1040.43,2040.43 1053.4,2053.4 1053.4,2074.9 1047.36,2080.93 1047.36,2106.36 1081,2140 v1(1081,2159) ; R17.2@1082,2252.99 R17.2@1082,2255.71 1082,2274 v1(1095,2287)
  BOTTOM w4: v1@1082,2158 1095,2171 v1(1095,2287)
NetJ1_8: J1.8 R65.1 | length 159.6
  TOP w4: J1.8@1040.43,1773.27 1040.43,1732.08 1063.2,1709.31 1063.2,1628.66 R65.1@1059.25,1624.71
NetJ1_9: J1.9 R75.2 | length 1335.3
  TOP w4: J1.9@1020.33,1999.06 1020.33,1958.33 1013,1951 1013,1944 1020,1937 v1(1034,1937) ; v1(1136,1158) 1147,1147 1174,1147 1202,1175 1236.77,1175 1243.76,1168.01 1250,1168.01 R75.2@1251,1168.01
  BOTTOM w4: v1(1034,1937) 1032.71,1937 1024.26,1928.55 1024.26,1911.21 1020.06,1907 1004,1907 1000,1903 1000,1887 1004,1883 1022,1883 1027,1878 1027,1839.85 1000.3,1813.15 1000.3,1672.56 1093,1579.86 1093,1407 1041.5,1355.5 1041.5,1348.5 1056,1334 1056,1322 1051,1317 1041,1317 1026,1332 1018,1332 1013.7,1327.7 1013.7,1311.67 1008,1305.97 1008,1287 1020,1275 1036.59,1275 1045.59,1266 1050.68,1260.91 1057.47,1260.91 1061.02,1264.46 1067.81,1264.46 1077.99,1254.28 1077.99,1247.49 1071.05,1240.54 1057.79,1227.29 1057.79,1220.5 1067.98,1210.32 1074.76,1210.32 1088.02,1223.57 1093.94,1229.5 1100.73,1229.5 1110.91,1219.32 1110.91,1212.53 ; 1108.69,1210.31 1110.91,1212.53 ; v1(1136,1158) 1136.6,1158.6 1136.6,1182.72 1132.71,1186.61 1116.18,1186.61 1107.39,1195.41 1107.39,1204.21 1107.39,1209 1110.91,1212.53
NetJ1_10: J1.10 R64.1 | length 151
  TOP w4: J1.10@1020.74,1773.27 1020.74,1630.58 R64.1@1026.61,1624.71
NetJ1_11: J1.11 R28.2 | length 163.5
  TOP w4: R28.2@931.5,2116.41 931.5,2097.5 956.2,2072.8 986.2,2072.8 1001.06,2057.94 J1.11@1001.06,1999.25
NetJ1_12: J1.12 R7.1 | length 675.6
  TOP w4: J1.12@1001.06,1773.27 1001.06,1773.46 1001.06,1815.06 1026,1840 v1(1075,1840) ; R7.1@1161.25,2255.71 1161.25,2292.25 v1(1166,2297)
  BOTTOM w4: v1(1075,1840) 1092,1857 1092,1869 1156,1933 1156,2052.85 1180,2076.85 1180,2283 v1(1166,2297)
NetJ1_13: J1.13 R27.2 | length 167
  TOP w10: 971,2058 981.37,2047.63 J1.13@981.37,1999.25
  TOP w15: R27.2@898.8,2116.51 898.8,2103.7 944.5,2058 971,2058
NetJ1_14: J1.14 R63.1 | length 172
  TOP w4: R63.1@962.11,1624.71 1000,1662.6 1000,1713.39 981.37,1732.02 J1.14@981.37,1773.27
NetJ1_15: J1.15 R54.2 | length 142.8
  TOP w4: J1.15@961.69,1999.25 961.69,1999.06 961.69,1945.31 978.71,1928.29 v1(996.42,1928.29)
  BOTTOM w4: R54.2@984,1886.99 984,1917 995.29,1928.29 v1(996.42,1928.29)
NetJ1_16: J1.16 R62.1 | length 161.7
  TOP w4: R62.1@929.85,1624.71 929.85,1677.85 961.69,1709.69 J1.16@961.69,1773.27
NetJ1_17: J1.17 R55.2 | length 122.8
  TOP w4: J1.17@942,1999.25 942,1999.06 942,1938 v1(959,1921)
  BOTTOM w4: R55.2@951,1886.79 951,1913 v1(959,1921)
NetJ1_19: J1.19 R56.2 | length 114.5
  TOP w4: v1(919,1920) 922.32,1923.32 922.32,1999.06 J1.19@922.32,1999.25
  BOTTOM w4: R56.2@918.5,1886.29 918.5,1919.5 v1(919,1920)
NetJ1_21: J1.21 R57.2 | length 145
  TOP w4: v1(866,1914) 866,1916 902.63,1952.63 902.63,1999.06 J1.21@902.63,1999.25
  BOTTOM w4: v1(866,1914) 877.5,1914 878.5,1915 885.6,1907.9 R57.2@885.6,1886.29
NetJ1_23: J1.23 R179.2 | length 148.1
  TOP w4: R179.2@811,2117.51 882.95,2045.56 J1.23@882.95,1999.25
NetJ1_25: J1.25 R180.2 | length 165
  TOP w4: R180.2@777.7,2117.71 777.7,2115.3 R180.2@778,2115.01 804,2089 823,2089 863.26,2048.74 J1.25@863.26,1999.25
NetJ1_26: J1.26 R59.1 | length 167.6
  TOP w5.2: R59.1@833.05,1624.71 825.2,1632.56 825.2,1665.7 858.52,1699.02 858.52,1717.31 863.26,1722.05 J1.26@863.26,1773.27
NetJ1_27: J1.27 R181.2 | length 276.9
  TOP w4: R181.2@753.5,2221.31 753.5,2203.5 762.73,2194.27 762.73,2099.27 767,2095 786.69,2095 805.69,2076 816,2076 843.58,2048.42 J1.27@843.58,1999.25
NetJ1_28: J1.28 R58.1 | length 176.8
  TOP w5.2: R58.1@800.55,1624.71 811.71,1624.71 815,1628 815,1669.92 822.85,1677.77 ; 822.85,1677.78 848.32,1703.25 848.32,1717.31 843.58,1722.05 J1.28@843.58,1773.27
NetJ1_29: J1.29 R182.2 | length 163
  TOP w4: R182.2@745,2112.01 R182.2@745,2109.01 745,2094 753,2086 783,2086 823.89,2045.11 J1.29@823.89,1999.25
NetJ1_31: J1.31 R183.2 | length 279.2
  TOP w4: R183.2@721,2221.71 721,2195 727.8,2188.2 727.8,2087.2 741,2074 779,2074 804.21,2048.79 J1.31@804.21,1999.25
NetJ1_33: J1.33 R184.2 | length 168.3
  TOP w4: R184.2@712,2117.01 712,2085 734,2063 769,2063 784.52,2047.48 J1.33@784.52,1999.25
NetJ1_44: J1.44 R53.1 | length 168.4
  TOP w5.2: R53.1@638.25,1624.71 638.25,1662.24 680.5,1704.49 680.5,1718.99 686.1,1724.59 J1.44@686.1,1773.27
NetJ1_46: J1.46 R52.1 | length 176.9
  TOP w5.2: R52.1@605.75,1624.71 628.05,1647.01 628.05,1666.47 670.3,1708.72 670.3,1719.2 666.41,1723.09 J1.46@666.41,1773.27
NetJ1_50: J1.50 R51.1 | length 177.5
  TOP w5.2: R51.1@573.25,1624.71 565.2,1632.76 565.2,1644.71 622,1701.51 622,1720.51 627.04,1725.55 J1.50@627.04,1773.27
NetJ1_51: J1.51 R23.2 | length 127.7
  TOP w4: R23.2@582.61,2116.73 590,2109.34 590,2058 607.36,2040.64 J1.51@607.36,1999.25
NetJ1_52: J1.52 R50.1 | length 187.2
  TOP w5.2: R50.1@540.75,1624.71 553.36,1624.71 556,1627.35 556,1649.94 611.8,1705.74 611.8,1719.71 607.36,1724.15 J1.52@607.36,1773.27
NetJ1_53: J1.53 R22.2 | length 137.5
  TOP w4: R22.2@550.11,2116.73 544.7,2111.32 544.7,2083.31 587.67,2040.34 J1.53@587.67,1999.25
NetJ1_55: J1.55 R33.2 | length 138
  TOP w4: R33.2@517.39,2116.29 535,2098.68 535,2073 567.99,2040.01 J1.55@567.99,1999.25
NetJ1_56: J1.56 R49.1 | length 182.6
  TOP w5.2: R49.1@508.25,1624.71 497.03,1635.93 497.03,1642.53 563.2,1708.7 563.2,1717.88 567.99,1722.67 J1.56@567.99,1773.27
NetJ1_57: J1.57 R21.2 | length 164.6
  TOP w4: R21.2@484.35,2116.73 480,2112.38 480,2080.01 495.01,2065 524,2065 548.3,2040.7 J1.57@548.3,1999.25
NetJ1_58: J1.58 R48.1 | length 182.6
  TOP w5.2: R48.1@475.61,1624.71 486.83,1635.93 486.83,1646.76 553,1712.93 553,1717.35 548.3,1722.05 J1.58@548.3,1773.27
NetJ1_59: J1.59 R20.2 | length 165.6
  TOP w4: R20.2@452.11,2116.73 452.11,2087.89 485,2055 513.01,2055 528.62,2039.39 J1.59@528.62,1999.25
NetJ2_1: J2.1 R111.2 | length 58.2
  TOP w15: R111.2@2155.99,369 2155.99,340.01 2156,315.04 J2.1@2159,312.04
NetJ3_1: J3.1 R85.2 U3.7 | length 1034
  TOP w7: v1(1111,585) 1179.1,653.1 1179.1,693.8 1163.2,709.7 1158,709.7 1157,709.7 1141.31,725.39 U3.7@1141.31,798.65
  BOTTOM w7: J3.1@808.4,-25.28 865.72,-25.28 1079,188 1079,435 1097.7,453.7 1097.7,501.68 1094,505.38 1094,569 1110,585 v1(1111,585)
NetJ3_3: J3.3 R87.1 U3.6 | length 1242
  TOP w7: v1(1068,513) 1054,527 1054,690 1075.89,711.89 1091.31,727.31 U3.6@1091.31,798.65
  BOTTOM w7: J3.3@532.8,-25.28 593.08,35 868,35 1062,229 1062,435.71 1085,458.71 1085,496 v1(1068,513)
NetJ5_1: J5.1 R19.2 | length 203
  TOP w4: v1(412,2079) 412,2095 419.25,2102.25 R19.2@419.25,2116.73
  BOTTOM w4: v1(412,2079) 469.5,2079 527.5,2021 J5.1@527.5,1998.28
NetJ5_3: J5.3 R24.2 | length 112.9
  BOTTOM w4: J5.3@627.5,1998.28 628.11,1997.67 R24.2@628.11,1885.6
NetJ5_5: J5.5 R25.2 | length 120.8
  BOTTOM w4: J5.5@727.5,1998.28 742.81,1982.97 R25.2@742.81,1883.8
NetJ5_6: J5.6 R1.1 | length 449.8
  BOTTOM w4: J5.6@727.5,2220.72 727.5,2244.5 770.5,2287.5 823.1,2287.5 902.5,2366.9 1076,2366.9 1082.91,2359.99 R1.1@1100,2359.99
NetJ5_8: J5.8 R9.1 | length 102
  TOP w4: v1(791.2,2256.2) 792.69,2254.71 R9.1@829.75,2254.71
  BOTTOM w4: v1(791.2,2256.2) 812.2,2256.2 827.5,2240.9 J5.8@827.5,2220.72
NetJ5_9: J5.9 R26.2 | length 152.1
  TOP w4: R26.2@866.7,2116.61 866.7,2096.7 v1(887.4,2076)
  BOTTOM w4: v1(887.4,2076) 902,2076 927.5,2050.5 J5.9@927.5,1998.28
NetJ5_10: J5.10 R2.1 | length 201.2
  TOP w4: v1(902.66,2328) 930.05,2300.61 R2.1@930.05,2255.71
  BOTTOM w4: v1(902.66,2328) 927.5,2303.16 J5.10@927.5,2220.72
NetJ5_11: J5.11 R18.2 | length 124
  TOP w4: R18.2@1028.21,2117.08 1028.21,2096.79 1034.1,2090.9 v1(1034.1,2061)
  BOTTOM w4: J5.11@1027.5,1998.28 1034.1,2004.88 v1(1034.1,2061)
NetJ5_12: J5.12 R4.1 | length 118
  TOP w4: R4.1@1022.55,2255.71 1022.55,2273.55 v1(1040,2291)
  BOTTOM w4: J5.12@1027.5,2220.72 1027.5,2278.5 v1(1040,2291)
NetJ5_13: J5.13 R31.2 | length 145.3
  TOP w4: v1(1155,2079) 1166,2079 1176.75,2089.75 R31.2@1176.75,2116.73
  BOTTOM w4: J5.13@1127.5,1998.28 1127.5,2040.5 1155,2068 v1(1155,2079)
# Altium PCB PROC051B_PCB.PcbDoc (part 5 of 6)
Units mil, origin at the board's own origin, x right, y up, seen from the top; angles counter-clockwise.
Board outline 3304.03 x 2647.77 mil, 6 copper layers (TOP, L2, L3, L4, L5, BOTTOM), stack 55.54 mil thick; 356 components, 272 nets, 1247 pads, 1391 vias.

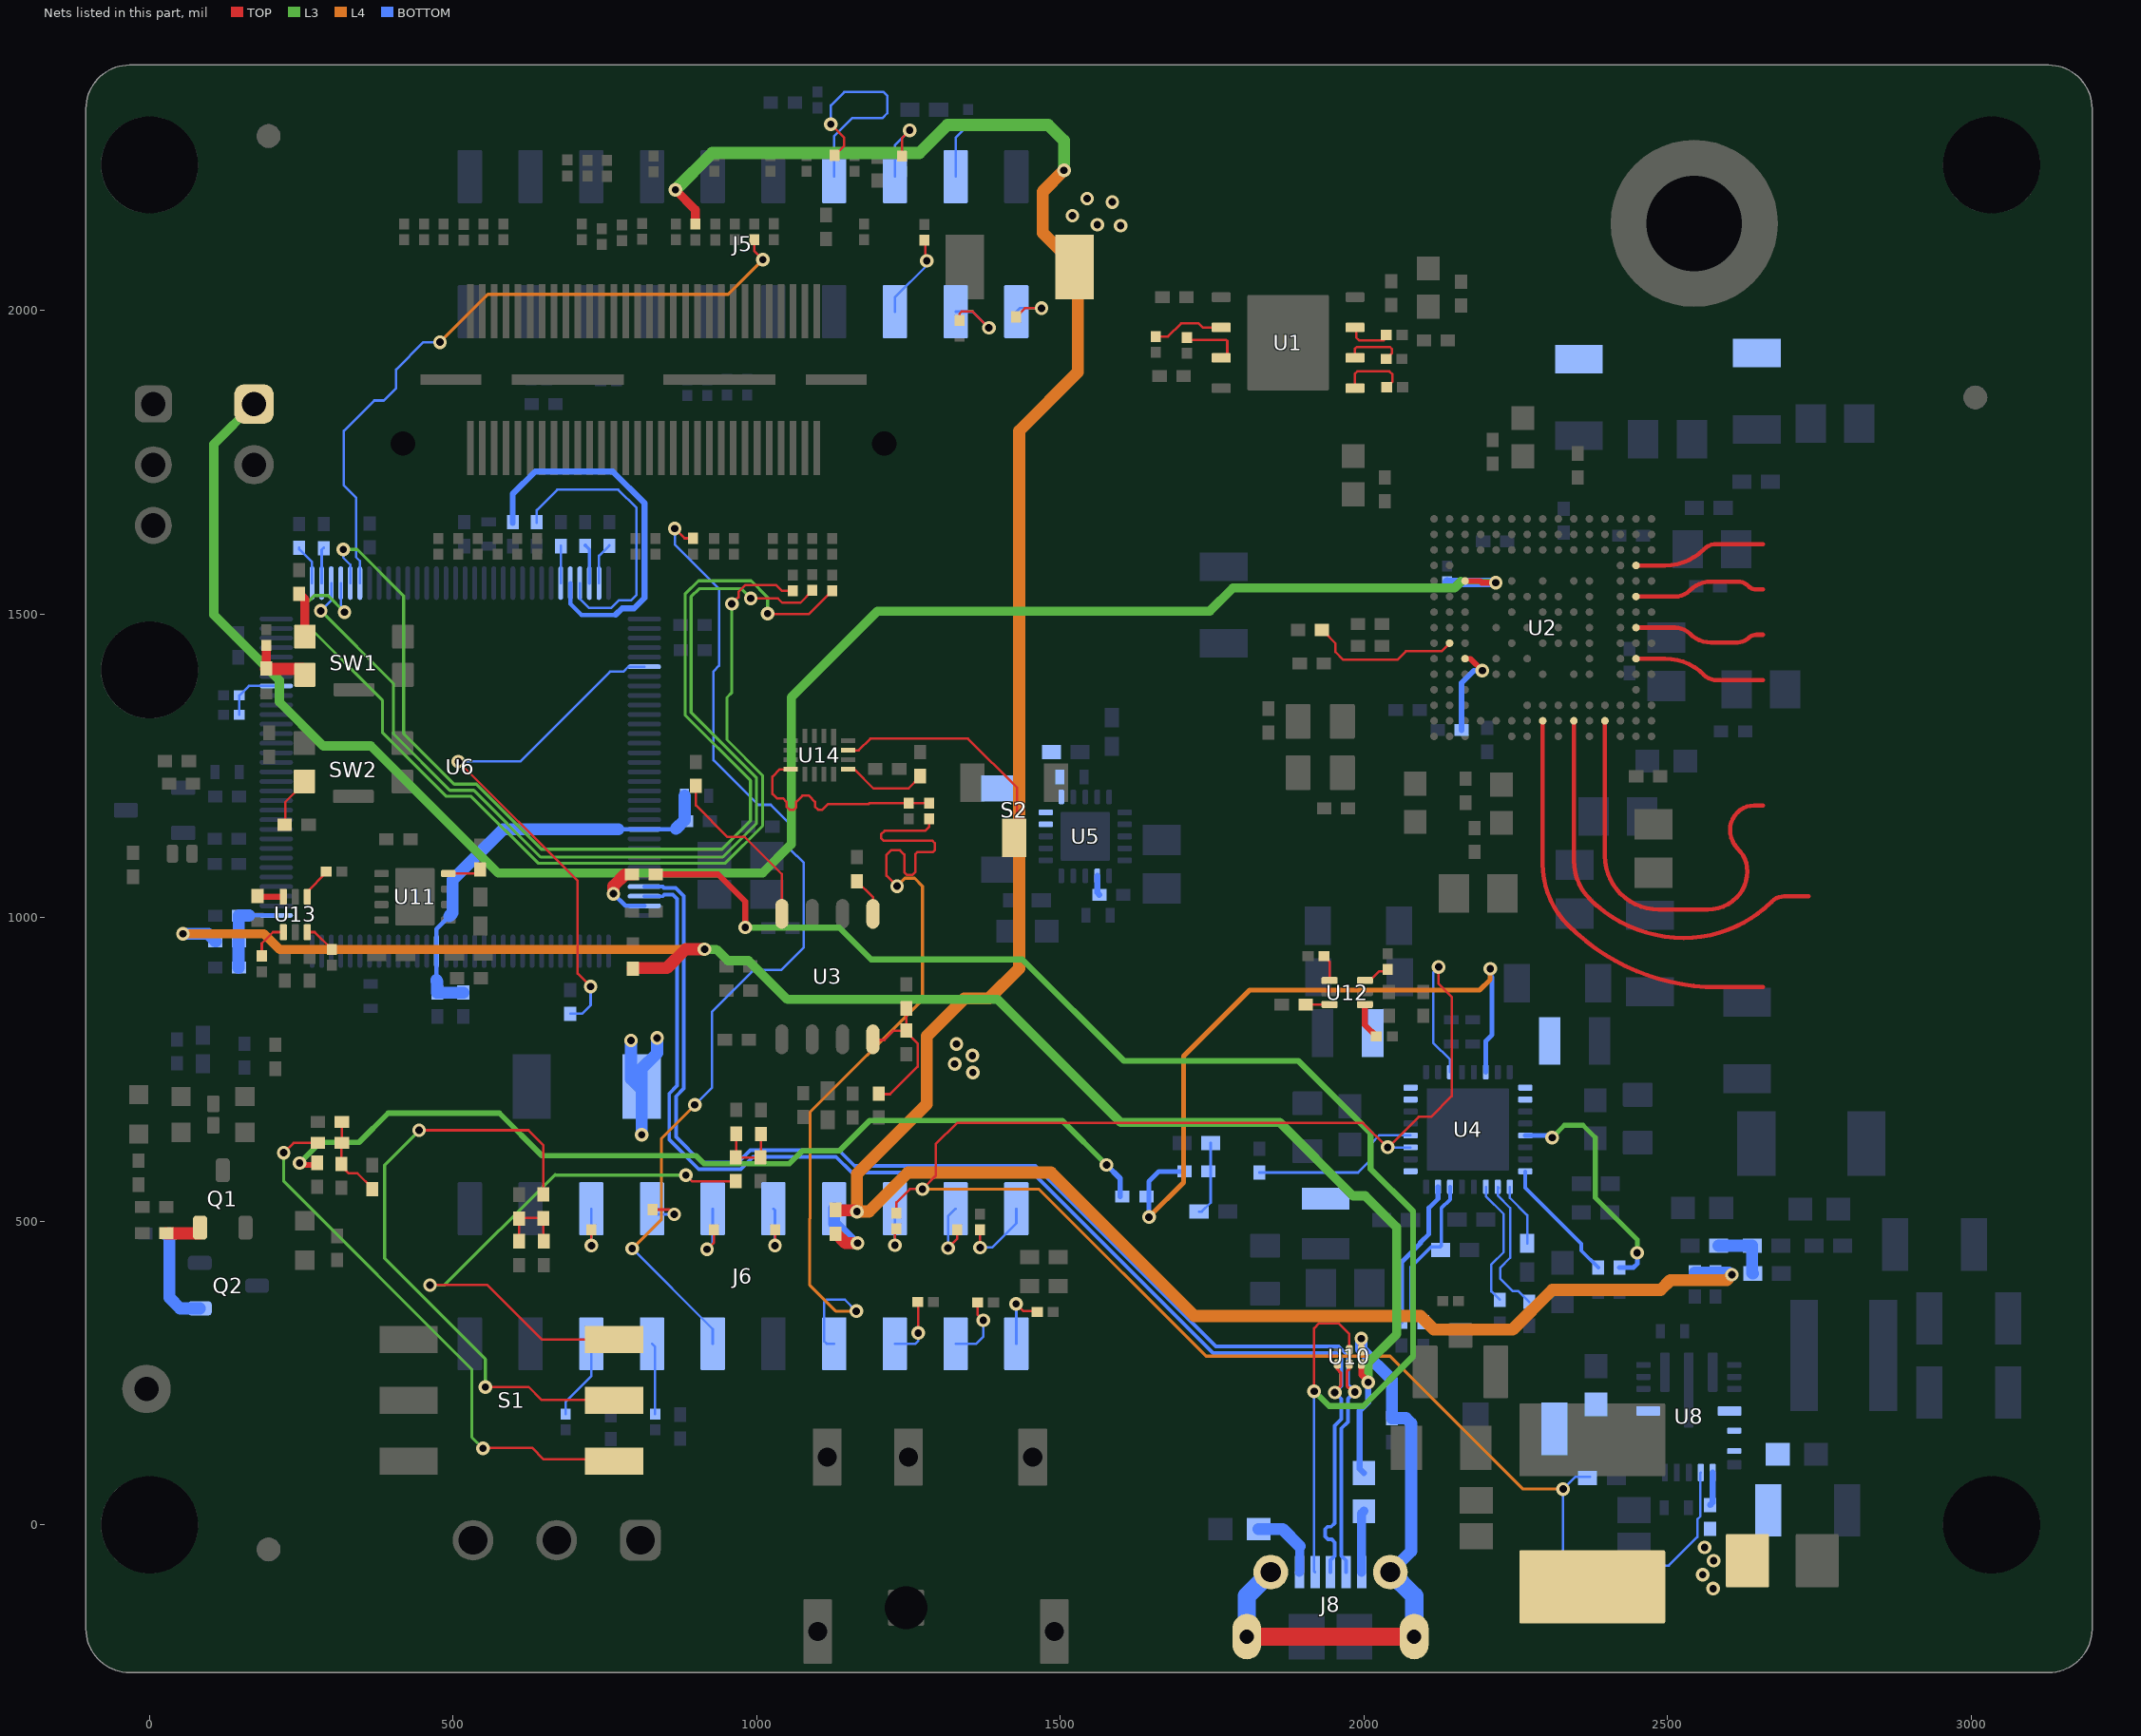
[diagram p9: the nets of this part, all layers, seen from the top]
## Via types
v1: diameter 22.4, hole 12.2, TOP to BOTTOM, tented both sides, 729 vias
v2: diameter 13.77/15.74 (per signal layer), hole 5.9, TOP to L2, tented both sides, 620 vias
v3: diameter 19.68, hole 7.87, TOP to BOTTOM, 25 vias
v4: diameter 22.4, hole 12.1, TOP to BOTTOM, tented both sides, 7 vias
v5: diameter 19.68, hole 7.87, TOP to BOTTOM, tented both sides, 5 vias
v6: diameter 16, hole 8, TOP to BOTTOM, tented both sides, 4 vias
v7: diameter 22.4/22.4/22.4/22.4/22.4/22.4 (per signal layer), hole 12.2, TOP to BOTTOM, tented both sides, 1 vias

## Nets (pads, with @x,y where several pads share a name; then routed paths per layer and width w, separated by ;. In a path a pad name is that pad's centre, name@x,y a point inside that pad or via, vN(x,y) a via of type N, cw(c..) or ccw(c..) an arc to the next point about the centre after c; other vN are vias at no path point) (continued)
NetJ5_14: J5.14 R6.1 | length 401.4
  TOP w4: v1(1122,2307) 1144,2285 1144,2271.66 R6.1@1128.05,2255.71
  BOTTOM w4: v1(1122,2307) 1122,2338 1144,2360 1209,2360 1215,2354 1215,2325 1207,2317 1157,2317 1127.5,2287.5 J5.14@1127.5,2220.72
NetJ5_15: J5.15 R32.2 | length 141.2
  TOP w4: R32.2@1277.55,2116.73 1278,2116.28 1278,2116.01 1278,2084 v1(1280,2082)
  BOTTOM w4: J5.15@1227.5,1998.28 1227.5,2021.5 1280,2074 v1(1280,2082)
NetJ5_16: J5.16 R10.1 | length 134
  TOP w4: R10.1@1239.25,2254.71 1239.25,2284.25 v1(1252,2297)
  BOTTOM w4: J5.16@1227.5,2220.72 1227.5,2272.5 v1(1252,2297)
NetJ5_17: J5.17 R35.2 | length 137.7
  TOP w4: R35.2@1334,1983.99 1334,1995 1337.5,1998.5 1355.59,1998.5 v1(1382.33,1971.76)
  BOTTOM w4: J5.17@1327.5,1998.28 1355.81,1998.28 v1(1382.33,1971.76)
NetJ5_18: J5.18 R8.1 | length 92.8
  BOTTOM w4: J5.18@1327.5,2220.72 1327.5,2284.51 R8.1@1348,2305.01
NetJ5_19: J5.19 R36.2 | length 91.5
  TOP w4: R36.2@1427.25,1989.71 1441.54,2004 v1(1469,2004)
  BOTTOM w4: J5.19@1427.5,1998.28 1433.22,2004 v1(1469,2004)
NetJ6_5: J6.5 R169.2 | length 133.6
  BOTTOM w4: R169.2@685.13,182.27 685.13,202.33 727.5,244.7 J6.5@727.5,298.28
NetJ6_6: J6.6 R104.1 | length 87.1
  TOP w4: v1(727.75,460) R104.1@727.75,486.29
  BOTTOM w4: J6.6@727.5,520.72 727.5,460.25 v1(727.75,460)
NetJ6_7: J6.7 R166.2 | length 118.2
  BOTTOM w4: J6.7@827.5,298.28 832.75,293.03 R166.2@832.75,182.27
NetJ6_8: J6.8 R94.1 | length 79.3
  TOP w4: R94.1@828.25,519.29 856.21,519.29 v1(864,511.5)
  BOTTOM w4: J6.8@827.5,520.72 836.72,511.5 v1(864,511.5)
NetJ6_9: J6.9 R165.2 | length 1685.6
  TOP w4: v1(865,1641) 881.01,1624.99 R165.2@895,1624.99
  L4 w5: v1(795,455) 843.13,503.13 843.13,636.71 897.9,691.48 v1(897.9,691.7)
  BOTTOM w4: v1(795,455) 927.5,322.5 J6.9@927.5,298.28 ; v1(865,1641) 865,1615 938,1542 938,1415 928.8,1405.8 928.8,1259.48 1002.28,1186 1023,1186 1056,1153 1056,1111.72 1065.52,1102.2 1065.95,1102.2 1077.5,1090.66 1077.5,951.5 1040,914 995,914 926,845 926,719.8 v1(897.9,691.7)
NetJ6_10: J6.10 R105.1 | length 108
  TOP w4: v1(918,453.9) 929.75,465.65 R105.1@929.75,486.29
  BOTTOM w4: v1(918,453.9) 927.5,463.4 J6.10@927.5,520.72
NetJ6_12: J6.12 R106.1 | length 88.1
  TOP w4: v1(1030,460) 1030.25,460.25 R106.1@1030.25,486.29
  BOTTOM w4: J6.12@1027.5,520.72 1030,518.22 v1(1030,460)
NetJ6_13: J6.13 R76.2 | length 1443.2
  TOP w4: v1(1231,1052) 1213.64,1069.36 1213.64,1103.64 1221,1111 1236.1,1111 1243,1104.1 1243,1075.1 1247.6,1070.5 1256.1,1070.5 1261.5,1075.9 1261.5,1105 1265,1108.5 1290.5,1108.5 1293,1111 1293,1123 1288.87,1127.13 1208.6,1127.13 1204.6,1131.13 1204.6,1137.29 1210.44,1143.13 1277.13,1143.13 1284,1150 R76.2@1284,1163.01
  L4 w5: v1(1164,352) 1130,352 1087.3,394.7 1087.3,504.44 1087.7,504.84 1087.7,679.7 1273,865 1273,1052 1260,1065 1244,1065 v1(1231,1052)
  BOTTOM w4: J6.13@1127.5,298.28 1115,298.28 1111,302.28 1111,367 1115,371 1145,371 v1(1164,352)
NetJ6_14: J6.14 R107.1 | length 119.2
  TOP w20: R107.1@1129.75,480.38 1130.14,479.99 1146.13,464 v1(1166,464)
  BOTTOM w20: J6.14@1127.5,520.72 1127.5,496.5 1160,464 v1(1166,464)
NetJ6_15: J6.15 R164.2 | length 104.9
  TOP w4: R164.2@1265.01,367 1266,366.01 v1(1266,316)
  BOTTOM w4: J6.15@1227.5,298.28 1261.28,298.28 1266,303 v1(1266,316)
NetJ6_16: J6.16 R102.1 | length 88.1
  TOP w4: v1(1227.5,460.5) 1227.5,484.54 R102.1@1230.25,487.29
  BOTTOM w4: v1(1227.5,460.5) J6.16@1227.5,520.72
NetJ6_17: J6.17 R163.2 | length 110.2
  TOP w4: R163.2@1364.01,366 1364.02,345.98 v1(1373,337)
  BOTTOM w4: J6.17@1327.5,298.28 1361.44,298.28 1373,309.84 v1(1373,337)
NetJ6_18: J6.18 R108.1 | length 106.3
  TOP w4: v1(1315,456) 1330.35,471.35 R108.1@1330.35,486.09
  BOTTOM w4: v1(1315,456) 1315,508.22 J6.18@1327.5,520.72
NetJ6_19: J6.19 R162.2 | length 107.6
  TOP w4: v1(1427,364) 1439,352 1458.01,352 1459.51,353.5 R162.2@1462.01,356
  BOTTOM w4: v1(1427,364) 1427.5,363.5 J6.19@1427.5,298.28
NetJ6_20: J6.20 R109.1 | length 129.5
  TOP w4: v1(1367.85,456.8) R109.1@1367.85,486.09
  BOTTOM w4: v1(1367.85,456.8) 1387.61,456.8 1427.5,496.69 J6.20@1427.5,520.72
NetJ8_1: J8.1 R161.1 | length 101.9
  BOTTOM w15: J8.1@1996.18,-77.86 1996.18,18.68 R161.1@2000,22.5
NetJ8_5: J8.5 R175.2 | length 122
  BOTTOM w15: J8.5@1893.82,-77.86 1894,-77.68 1894,-35
  BOTTOM w20: R175.2@1826.5,-7 1866,-7 1894,-35
NetJ8_6: J8.6 J8.9 J8.10 J8.11 R174.2 U10.1 | length 987.2
  TOP w10: U10.1@1995.69,287.59 v1(1995.69,307)
  TOP w30: J8.9@1807.2,-184.16 J8.6@2082.8,-184.16
  BOTTOM w20: v1(1995.69,307) 1995.69,289.31 2046,239 R174.2@2046,175.69 2069.31,175.69 2078,167 2078,-43.29 J8.11@2043.43,-77.86
  BOTTOM w30: J8.9@1807.2,-184.16 1807.2,-117.23 J8.10@1846.57,-77.86 ; J8.11@2043.43,-77.86 2082.8,-117.23 J8.6@2082.8,-184.16
NetL2_1: L2.1 U4.25 U4.26
NetL3_1: L3.1 U4.15 U4.16
NetL4_2: L4.2 U4.9
NetQ1_1: Q1.1 R116.2 | length 67.6
  TOP w20: R116.2@26.68,480.33 R116.2@27.47,480.33 83.18,480.33 Q1.1@83.18,489.51 Q1.1@83.18,491.47
NetQ2_1: Q2.1 R160.2 | length 163.1
  BOTTOM w20: R160.2@32.69,480 32.69,374.31 50.4,356.6 Q2.1@82.76,356.6
NetR3_1: R3.1 U12.3 | length 40.2
  TOP w4: R3.1@1903.2,857.1 1903.31,857.21 1903.99,857.21 U12.3@1943.37,857.22
NetR5_2: R5.2 U12.1 | length 44.3
  TOP w4: R5.2@1933.99,937 1943.37,927.63 U12.1@1943.37,896.59
NetR11_2: R11.2 U3.1 | length 64.9
  TOP w4: R11.2@1165,1060.31 1191.31,1034 U3.1@1191.31,1006.33
NetR12_2: R12.2 U3.4 | length 285.1
  TOP w4: R12.2@900,1217.31 900,1185 952,1133 980.31,1133 1041.31,1072 U3.4@1041.31,1007.31
NetR39_2: R39.2 U1.2 | length 119.7
  TOP w4: R39.2@1656.9,1957.49 1677.49,1957.49 1699,1979 1727.76,1979 1734.58,1972.18 U1.2@1764.89,1972.18
NetR40_1: R40.1 U1.7 | length 69.4
  TOP w4: U1.7@1987.33,1972.18 1987.33,1955.67 1992,1951 2032.84,1951 R40.1@2036.69,1954.85
NetR42_2: R42.2 U1.3 | length 107.1
  TOP w4: R42.2@1708.5,1955.79 1712.29,1952 1773,1952 1775,1950 1775,1925 1772.18,1922.18 U1.3@1764.89,1922.18 U1.3@1762.93,1922.18
NetR44_1: R44.1 U1.6 | length 98.7
  TOP w4: U1.6@1985.37,1922.18 1985.37,1937.37 1988,1940 2043,1940 2046,1937 2046,1929.66 R44.1@2036.69,1920.35
NetR45_1: R45.1 U1.5 | length 114.4
  TOP w4: U1.5@1985.37,1872.18 1985.37,1896.37 1989,1900 2042,1900 2047,1895 2047,1883.16 R45.1@2037.69,1873.85
NetR47_1: R47.1 U2.G14 | length 247.2
  TOP w4: R47.1@1931.68,1469 1936,1469 1953,1452 1953,1437.78 1965.85,1424.93 2054.93,1424.93 2069.02,1439.02 2127.72,1439.02 U2.G14@2141.01,1452.31
NetR68_1: R68.1 SW1.4 | length 69.3
  TOP w15: R68.1@246.04,1534.25 246.43,1533.86 255.94,1524.35 SW1.4@255.94,1469.02
NetR72_1: R72.1 R73.2 SW1.2 | length 104.1
  TOP w15: R73.2@192.05,1409.82 192.44,1410.21 192.5,1410.27 192.5,1410.61 R72.1@192.5,1448.26
  TOP w20: R73.2@192.05,1409.82 252.14,1409.82 SW1.2@255.94,1406.02
NetR79_2: R79.2 SW2.2 | length 90.4
  TOP w4: R79.2@223.35,1153.14 223.35,1190.35 252.04,1219.04 252.04,1224.5 252.04,1227.45 SW2.2@254.99,1230.4
NetR81_1: R81.1 U2.F13 | length 157
  TOP w9: U2.F13@2166.6,1426.72 2175.28,1426.72 v1(2195,1407)
  BOTTOM w9: R81.1@2160.68,1309 2160.68,1386.68 2181,1407 v1(2195,1407)
NetR82_2: R82.2 U8.18 | length 55.3
  BOTTOM w10: R82.2@2570,32.69 2574.37,37.06 U8.18@2574.37,86.19
NetR86_1: R86.1 R177.2 R178.1 U3.8 | length 248.6
  TOP w4: U3.8@1191.31,798.65 1210.11,798.65 1225.06,813.6 R86.1@1246.3,813.6 ; R178.1@1200.8,709.5 1219.7,709.5 1265,754.8 1265,793 1246.3,811.7 R86.1@1246.3,813.6 ; R177.2@1246.5,851.45 R177.2@1246.5,850.66 1246.5,832 1246.3,831.8 R86.1@1246.3,814.39 R86.1@1246.3,813.6
NetR88_2: R88.2 R89.2 R92.1 R93.1 | length 120.8
  TOP w4: R88.2@966.12,644.95 R88.2@966.12,644.16 966.12,605.53 966.12,605.25 966.01,605.14 965.62,604.75 1005.82,604.75 1006.21,605.14 R93.1@1006.58,605.51 ; R93.1@1006.58,605.53 R89.2@1006.58,643.86 R89.2@1006.58,644.65
NetR92_2: R92.2 S1.3 | length 924.1
  TOP w4: v1(462,395) 556.29,395 646.29,305 S1.3@765.29,305 ; v1(883.4,576) 893.23,566.16 R92.2@965.62,566.16
  L3 w5: v1(462,395) 486,395 668,577 669,576 v1(883.4,576)
NetR95_1: R95.1 R96.2 R112.1 R113.2 | length 118.5
  TOP w4: R113.2@608.92,466.45 608.78,466.59 608.78,467.24 R96.2@608.78,504.56 608.78,505.35 648.52,505.35 648.82,505.65 R95.1@648.82,504.86 648.82,467.24 648.82,466.95 648.93,466.84 R112.1@649.32,466.45
NetR95_2: R95.2 S1.2 | length 1056.1
  TOP w4: v1(444,650) 624,650 648.82,625.18 R95.2@648.82,544.24 ; v1(553,227) 624.29,227 645.29,206 743.88,206 743.88,205 743.88,191.88 765.29,191.88 766.51,191.88 S1.2@772.46,197.83
  L3 w5: v1(444,650) 444,649.64 387.08,592.72 387.08,438.92 553,273 v1(553,227)
NetR98_2: R98.2 R99.1 R101.1 R114.2 | length 137.8
  TOP w4: R114.2@316.69,662 R99.1@316.68,629 316,628.32 R98.2@316,594.69 316,591 328,579 342.53,579 R101.1@367.28,554.25
NetR99_2: R99.2 S1.1 | length 911.6
  TOP w4: v1(221,613) 237,629 R99.2@277.31,629 ; v1(549,126) 550,127 630,127 649,108 762.29,108 S1.1@765.29,105
  L3 w5: v1(221,613) 221,566 530.72,256.28 530.72,144.28 v1(549,126)
NetR119_2: R119.2 U4.2 | length 232.5
  BOTTOM w4: U4.2@2222.2,555.06 U4.2@2220.48,556.78 2220.48,542.52 2241,522 2241,440.03 2224.3,423.33 2224.3,405.7 2244.6,385.4 2253.97,385.4 R119.2@2272,367.37
NetR120_2: R120.2 U5.12 | length 32.6
  BOTTOM w10: U5.12@1560.72,1069.04 1560.68,1041.63 R120.2@1564.31,1038
NetR121_2: R121.2 U4.3 | length 212.3
  BOTTOM w4: U4.3@2200.8,556.78 2200.8,541.2 2230,512 2230,449 2210,429 2210,384.69 R121.2@2224,370.69
NetR123_1: R123.1 U6.63 | length 69.2
  BOTTOM w4: U6.63@740.14,1551.19 740.14,1596.11 756.89,1612.86 R123.1@757.28,1613.25
NetR124_1: R124.1 U6.61 | length 488.4
  BOTTOM w4: R124.1@637.72,1650.75 R124.1@637.72,1651.53 637.72,1671.22 671.5,1705 772,1705 802,1675 802,1532 792.8,1522.8 772.8,1522.8 760.5,1510.5 723.5,1510.5 709,1525 709,1550.83 U6.61@708.64,1551.19
NetR125_2: R125.2 U6.59 | length 61.9
  BOTTOM w4: U6.59@677.14,1551.19 677.14,1612.16 677.14,1612.57 R125.2@677.52,1612.95
NetR126_1: R126.1 U6.62 | length 64.8
  BOTTOM w6: R126.1@717.68,1613.25 718.07,1612.86 724.39,1606.54 U6.62@724.39,1551.19
NetR127_1: R127.1 U6.60 | length 632.6
  BOTTOM w7: U6.60@692.89,1551.19 692.89,1517.05 710.94,1499 767.38,1499
  BOTTOM w10: R127.1@598.12,1650.75 R127.1@598.12,1651.53 598.12,1698.11 635.01,1735 763,1735 815,1683 815,1526.62 798.18,1509.8 778.18,1509.8 767.38,1499
NetR128_2: R128.2 U6.33 | length 67.5
  BOTTOM w4: R128.2@246.5,1609.95 R128.2@246.5,1609.16 246.5,1606.98 267.7,1585.78 U6.33@267.7,1551.19
NetR129_2: R129.2 U6.34 | length 59.9
  BOTTOM w4: U6.34@283.44,1551.19 283.44,1606.04 286.61,1609.21 R129.2@287,1609.6
NetR135_2: R135.2 R136.2 U6.25 | length 99.4
  BOTTOM w4: R136.2@147.77,1334.29 R135.2@147.77,1366.19 163.58,1382 208.54,1382 U6.25@208.64,1381.9
NetR139_2: R139.2 R146.1 R157.2 | length 101.5
  BOTTOM w20: R146.1@2584.24,460 R157.2@2639.38,460 2639.38,415 R139.2@2640.38,414
NetR142_1: R142.1 R149.1 U4.6 | length 266.5
  BOTTOM w6: R149.1@2098,333.68 2078,353.68 2078,425 2111,458 2125.54,458 2127.38,459.83 2127.38,521.38 2142,536 2142,556.52 U4.6@2141.74,556.78
NetR143_2: R143.2 U4.29 | length 396.8
  L3 w8: v1(2310,638) 2330.22,658.2 2360.79,658.2 2381.02,637.97 2381.02,538.98 2450,470 v1(2450,448.12)
  BOTTOM w8: U4.29@2265.76,641.43 v1@2306.57,641.43 ; R143.2@2421,423.69 2443.83,423.69 2450,429.86 v1(2450,448.12)
NetR144_2: R144.2 U4.12 | length 289.6
  BOTTOM w4: R144.2@1828,580.31 1990.31,580.31 2012.68,602.68 2012.68,629.11 2025,641.43 U4.12@2076.78,641.43
NetR148_1: R148.1 U4.7 | length 247
  BOTTOM w8: R148.1@2062,334.68 2062,432.67 2093.12,463.79 2093.12,465.12 2107,479 2107,522 2122.06,537.06 U4.7@2122.06,556.78
NetR152_1: R152.1 U6.95 | length 111.1
  TOP w20: v1(764,1039.5) 764,1052.41 783.09,1071.5 R152.1@794.32,1071.5 R152.1@795.1,1071.5
  BOTTOM w7: v1(764,1039.5) 783.81,1019.69 U6.95@814.94,1019.69
NetR155_1: R155.1 U6.70 | length 902.2
  TOP w4: v1(508.4,1257.3) 705,1060.7 705,908.2 v1(726.4,886.8)
  BOTTOM w4: v1(508.4,1257.3) 610.3,1257.3 758.3,1405.3 780.49,1405.3 788.58,1413.39 U6.70@814.94,1413.39 ; R155.1@692.78,842.25 712.74,842.25 726.4,855.91 v1(726.4,886.8)
NetR158_1: R158.1 U4.1 | length 105.1
  BOTTOM w4: U4.1@2240.17,556.78 2240.17,538.83 2269,510 R158.1@2269,463.62
NetR159_2: R159.2 U4.32 | length 208.5
  BOTTOM w6: U4.32@2265.76,582.37 2265.76,555.24 2358,463 2358,451.69 R159.2@2386,423.69
NetR167_2: R167.2 U12.4 | length 60.5
  TOP w10: U12.4@2001.63,857.22 2001.63,823.58 R167.2@2020.61,804.6
NetR168_1: R168.1 U12.6 | length 45
  TOP w4: U12.6@2001.63,896.59 2010.02,896.59 2025.33,911.9 2035.89,911.9 R168.1@2039,915.01
NetR186_1: R186.1 R189.1 R190.2 | length 123.7
  BOTTOM w4: R186.1@1728.38,516 1733,516 1747.62,530.62 1747.62,582 R190.2@1747.62,629
NetR188_1: R188.1 R189.2 U4.22 | length 1159.7
  L4 w8: v1(1646,507) 1703,564 1703,772 1811.8,880.8 2190.57,880.8 2208,898.23 v1(2208,916)
  BOTTOM w8: v1(1646,507) 1645.62,507.38 1645.62,541 1645.62,565.62 1662,582 R189.2@1700.38,582 ; U4.22@2200.8,745.76 2200.8,796.8 2211,807 2211,902 2208,905 v1(2208,916)
NetR194_2: R194.2 U11.8 | length 48.9
  TOP w4: U11.8@495.96,1072.89 544.7,1072.89 R194.2@544.9,1072.89
NetR197_1: R197.1 U13.3 | length 42.8
  TOP w10: R197.1@177.8,1035.3 178.57,1034.53 U13.3@220.32,1034.53
NetR198_2: R198.2 U13.1 | length 54.1
  TOP w4: U13.1@259.69,1034.53 259.69,1043.08 290.61,1074 R198.2@290.61,1075.8
NetR199_1: R199.1 U13.6 | length 52.4
  TOP w4: U13.6@259.69,976.27 271.82,976.27 R199.1@300.3,947.79
NetR201_1: R201.1 U13.4 | length 63.7
  TOP w4: R201.1@184.9,937.19 184.9,957.9 203.27,976.27 U13.4@220.32,976.27
NetR208_1: R208.1 U14.13 | length 140.9
  TOP w4: U14.13@1150.24,1244.38 1160.95,1244.38 1192.28,1213.05 1250.05,1213.05 1269,1232 R208.1@1269,1233.32
NetS2_2: S2.2 U14.15 | length 402.7
  TOP w4: U14.15@1150.24,1275.87 1167.87,1275.87 1187,1295 1348,1295 1428.9,1214.1 1428.9,1131.72 S2.2@1428.9,1131.45
PGOOD: R27.1 R107.2 R138.2 R141.2 | length 4452.9
  TOP w15: v1(866,2199) 898.8,2166.2 R27.1@898.8,2142.49
  TOP w20: R107.2@1129.75,518.18 1159.86,518.18 1162.04,516 v1(1165,516)
  L3 w20: v1(866,2199) 926.8,2259.8 1267.8,2259.8 1314,2306 1480,2306 1506,2280 v1(1506,2231)
  L4 w20: v1(1506,2231) 1471,2196 1471,2128 1529,2070 1529,1899 1432,1802 1432,916.53 1382.47,867 1342,867 1280,805 1280,693 1165,578 v1(1165,516) 1185,516 1249.2,580.2 1484.8,580.2 1721,344 2093,344 2115.2,321.8 2244.84,321.8 2310.3,387.27 2488.8,387.27 2504.73,403.2 2597.2,403.2 v1(2606,412)
  BOTTOM w20: R138.2@2545,415.69 R141.2@2579,415.69 2600.5,415.69 2604.18,412 v1(2606,412)
PMIC_CLK: R97.2 R188.2 | length 1547.6
  TOP w9: v1(247,596) 250.16,592.84 R97.2@275,592.84
  L3 w9: v1(247,596) 281,630 345,630 393,678 576,678 646,608 900,608 913,595 1054,595 1075,616 1136,616 1186,666 1503,666 v1(1576,593)
  BOTTOM w9: v1(1576,593) 1598.38,570.62 R188.2@1598.38,541
PMIC_EN1: R84.1 R102.2 U4.11 U4.19 U8.19 | length 3293.6
  TOP w4: R102.2@1230.25,513.27 1230.25,531.25 1252,553 v1(1273,553) 1294.81,574.81 1294.81,627.05 1329.76,662 1998,662 2038.5,621.5 2039,621 v1(2039,622) 2040,622 2090.24,672.24 2110.69,672.24 2144.44,705.99 2144.44,869.71 2123,891.16 v1(2123,919)
  L4 w5: v1(1273,553) 1465,553 1740,278 2043,278 2262,59 v1(2328,59)
  BOTTOM w4: v1@2040,621 2040.74,621.74 U4.11@2076.78,621.74 ; v1(2123,919) 2114,910 2114,794 2141.74,766.26 U4.19@2141.74,745.76 ; R84.1@2372.31,79 2368.38,79 2348,79 v1(2328,59) 2328,-48.6 2346.4,-67 2502,-67 2549,-20 2549,9 2554.16,14.16 2554.16,85.66 U8.19@2554.68,86.19
RX1: U2.M2 | length 312.8
  TOP w7.08: U2.M2@2448.09,1580.26 2496.4,1580.26 ; 2657.22,1615.6 2581.07,1615.6 ; 2496.4,1580.26 ccw(c2496.4,1669.28) 2559.79,1606.78 ; 2496.4,1580.26 ccw(c2496.4,1669.28) 2559.79,1606.78 ; 2559.79,1606.79 cw(c2581.07,1585.5) 2581.07,1615.6 ; 2559.79,1606.79 cw(c2581.07,1585.5) 2581.07,1615.6
RX2: U2.K2 | length 318.3
  TOP w7.08: U2.K2@2448.09,1529.08 2512.28,1529.08 ; 2656.92,1540.8 2646.47,1540.8 ; 2512.28,1529.08 ccw(c2512.28,1563.6) 2536.69,1539.19 ; 2512.28,1529.08 ccw(c2512.28,1563.6) 2536.69,1539.19 ; 2536.7,1539.19 cw(c2571.24,1504.66) 2571.24,1553.5 ; 2536.7,1539.19 cw(c2571.24,1504.66) 2571.24,1553.5 ; 2571.24,1553.5 2615.82,1553.5 ; 2615.82,1553.5 cw(c2615.82,1528.95) 2633.18,1546.31 ; 2615.82,1553.5 cw(c2615.82,1528.95) 2633.18,1546.31 ; 2633.19,1546.3 ccw(c2646.47,1559.58) 2646.47,1540.8 ; 2633.19,1546.3 ccw(c2646.47,1559.58) 2646.47,1540.8
RX3: U2.H2 | length 318.3
  TOP w7.08: U2.H2@2448.09,1477.9 2512.28,1477.9 ; 2656.92,1466.18 2646.47,1466.18 ; 2512.28,1477.9 cw(c2512.28,1443.38) 2536.69,1467.79 ; 2512.28,1477.9 cw(c2512.28,1443.38) 2536.69,1467.79 ; 2536.7,1467.79 ccw(c2571.24,1502.32) 2571.24,1453.48 ; 2536.7,1467.79 ccw(c2571.24,1502.32) 2571.24,1453.48 ; 2571.24,1453.48 2615.82,1453.48 ; 2615.82,1453.48 ccw(c2615.82,1478.03) 2633.18,1460.67 cw(c2615.82,1478.03) 2615.82,1453.48 ; 2646.47,1466.18 ccw(c2646.47,1447.4) 2633.19,1460.68 cw(c2646.47,1447.4) 2646.47,1466.18
RX4: U2.F2 | length 313.6
  TOP w7.08: U2.F2@2448.09,1426.72 2496.4,1426.72 ; 2657.4,1391.2 2581.51,1391.2 ; 2496.4,1426.72 cw(c2496.4,1337.7) 2559.79,1400.2 ; 2496.4,1426.72 cw(c2496.4,1337.7) 2559.79,1400.2 ; 2559.79,1400.19 ccw(c2581.5,1421.91) 2581.5,1391.2 ; 2559.79,1400.19 ccw(c2581.5,1421.91) 2581.5,1391.2
SPICLK1: R75.1 R76.1 U14.8 | length 370
  TOP w4: U14.8@1055.76,1244.38 1038.02,1244.38 1026,1232.36 1026,1204 1033.2,1196.8 1043.2,1196.8 1049,1191 1049,1183 1054,1178 1061,1178 1065,1182 1065,1190.8 1075.2,1201 1086,1201 1096,1191 1096,1183 1101,1178 1108,1178 1117,1187 1184,1187 1185.99,1188.99 R75.1@1250,1188.99 R76.1@1284,1188.99
TX1: U2.B4 | length 1074.1
  TOP w7.08: U2.B4@2396.91,1324.36 2396.91,1102.05 ; 2657.3,1184.9 2642.61,1184.9 ; 2396.91,1102.05 ccw(c2485.46,1102.05) 2485.46,1013.5 ; 2396.91,1102.05 ccw(c2485.46,1102.05) 2485.46,1013.5 ; 2485.46,1013.5 2566.65,1013.5 ; 2566.65,1013.5 ccw(c2566.65,1079.79) 2613.53,1032.92 cw(c2566.65,1079.79) 2566.65,1013.5 ; 2603.07,1144.8 cw(c2643.55,1144.8) 2614.93,1173.43 ; 2603.07,1144.78 ccw(c2647.37,1144.78) 2616.04,1113.46 ; 2603.07,1144.8 cw(c2643.55,1144.8) 2614.93,1173.43 ; 2603.07,1144.78 ccw(c2647.37,1144.78) 2616.04,1113.46 ; 2614.94,1173.43 cw(c2642.62,1145.76) 2642.61,1184.9 ; 2614.94,1173.43 cw(c2642.62,1145.76) 2642.61,1184.9 ; 2616.05,1113.46 cw(c2578.8,1076.22) 2631.47,1076.22 ; 2616.05,1113.46 cw(c2578.8,1076.22) 2631.47,1076.22 ; 2631.47,1076.22 cw(c2570.24,1076.22) 2613.54,1032.93 ccw(c2570.24,1076.22) 2631.47,1076.22
TX2: U2.B6 | length 1122.2
  TOP w7.08: U2.B6@2345.73,1324.36 2345.73,1094.33 ; 2732.11,1035.3 2692.06,1035.3 ; 2345.73,1094.33 ccw(c2435.71,1094.33) 2372.08,1030.71 ; 2345.73,1094.33 ccw(c2435.71,1094.33) 2372.08,1030.71 ; 2372.11,1030.68 ccw(c2526.5,1185.06) 2526.5,966.73 ; 2372.11,1030.68 ccw(c2526.5,1185.06) 2526.5,966.73 ; 2526.5,966.73 ccw(c2526.5,1172.53) 2672,1026.99 ; 2526.5,966.73 ccw(c2526.5,1172.53) 2672,1026.99 ; 2672.01,1026.99 cw(c2692.07,1006.94) 2692.06,1035.3 ; 2672.01,1026.99 cw(c2692.07,1006.94) 2692.06,1035.3
TX3: U2.B8 | length 1082.1
  TOP w7.08: U2.B8@2294.55,1324.36 2294.34,1324.15 2294.34,1089.06 ; 2657.3,885.68 2582.22,885.68 ; 2294.34,1089.06 ccw(c2437.96,1089.06) 2336.4,987.51 ; 2294.34,1089.06 ccw(c2437.96,1089.06) 2336.4,987.51 ; 2336.41,987.5 ccw(c2582.22,1233.3) 2582.22,885.68 ; 2336.41,987.5 ccw(c2582.22,1233.3) 2582.22,885.68
VBUS_1_DETECT: C69.2 R151.1 R153.2 U6.1 | length 147.8
  BOTTOM w7: 163.95,1003.95 U6.1@208.64,1003.95
  BOTTOM w20: R153.2@146.55,917.74 146.55,961.04 146.94,961.43 146.95,1003.56 C69.2@147.34,1003.56 163.56,1003.56 163.95,1003.95
VCC_LDO_OUT: C44.1 C72.1 L8.1 L9.1 R122.2 U5.1 U5.19 U5.20
VDDC_1: C62.1 C64.2 C74.2 C75.2 U6.87 U6.115 | length 697.8
  BOTTOM w7: 472.42,897.18 U6.115@472.42,944.89 472.42,981.42 493.6,1002.6 ; 771.82,1145.68 U6.87@814.94,1145.68 861.38,1145.68
  BOTTOM w20: 472.42,897.18 472.7,896.9 472.7,895.48 473.68,894.5 C75.2@473.68,876.84 473.68,876.45 C74.2@516.6,876.45 ; 493.6,1002.6 499,1008 499,1062.4 582.28,1145.68 771.82,1145.68 ; 866.81,1146.5 881.31,1161 C62.1@881.31,1201
VIN: C21.1 C23.1 C25.1 C26.1 C27.1 L7.2 R34.2 R82.1 R115.2 U8.4 U8.14 U8.15 U8.16 | length 257.4
  BOTTOM w20: v1(793,798) 793,734.55 808.05,719.5 R115.2@810.55,717 ; v1(810.55,642.45) R115.2@810.55,717 ; v1@836,801 836,777 810.55,751.55 R115.2@810.55,722 R115.2@810.55,717
  other v1: 2575,-105 2558,-82 2576,-59 2561,-37 1356,745 1326,759 1355,773 1329,792 836,802 1599.3,2140 1561,2141.5 1520,2156.5 1585.7,2178.9 1544,2184.5
VPP_1P7: C8.1 P7.1 U2.L13 | length 3156.7
  TOP w10: U2.L13@2166.6,1554.67 2191.27,1554.67 2194.09,1551.85 2194.24,1552 v1(2217,1552)
  L3 w10: 2159.8,1553.8 2215.2,1553.8 v1(2217,1552)
  L3 w15: P7.1@171.94,1846.15 105.82,1780.03 105.82,1499.09 213.8,1391.11 213.8,1355.42 286.12,1283.1 364.47,1283.1 573.87,1073.7 1009.7,1073.7 1056.9,1120.9 1056.9,1362.9 1199,1505 1746,1505 1784,1543 2149,1543 2159.8,1553.8
  BOTTOM w15: C8.1@2137,1553.01 2137.7,1552.3 2211.23,1552.3 2211.93,1553 2216,1553 v1(2217,1552)
XDSET_1_D_N: J8.2 U6.93 U10.5 | length 2172.5
  TOP w5.2: U10.5@1976,264.95 1976,256.44 1972.13,252.57 1972.13,228.91 1979.78,221.26 v1@1984,221.26
  BOTTOM w6: U6.93@814.94,1051.19 845.1,1051.19 847.07,1049.22 866.36,1049.22 880,1035.57 880,719 867,706 867,639 909,597 969,597 989.21,617.21 1135.21,617.21 1161.11,591.31 1458.82,591.31 1756.13,294 1958.56,294 1973.6,278.96 1973.6,230.4 v1(1985,219) 1973.58,207.58 1973.58,169.58 1962.9,158.9 1962.9,-50.9 1970.59,-58.59 J8.2@1970.59,-77.86
XDSET_1_D_P: J8.3 U6.94 U10.4 | length 2173.2
  TOP w5.2: v1@1952.28,219.26 1961.93,228.91 1961.93,250.83 1956.32,256.44 U10.4@1956.32,264.95
  BOTTOM w6: U6.94@814.94,1035.44 845.1,1035.44 847.87,1038.22 861.8,1038.22 869,1031.02 869,723.56 856,710.56 856,634.44 904.44,586 973.56,586 993.77,606.21 1130.66,606.21 1156.55,580.31 1454.26,580.31 1751.57,283 1954,283 1962.6,274.4 1962.6,228.6 v1(1952,218) 1962.58,207.42 1962.58,174.14 1951.9,163.45 1951.9,2.9 1946,-3 1940,-3 1936,-7 1936,-19 1941,-24 1947,-24 1951.9,-28.9 1951.9,-51.1 1945,-58 J8.3@1945,-77.86
XDSET_1_ID: J8.4 R152.2 U10.2 | length 2480.3
  TOP w4: v1(1918,220) 1918,324 1926.2,332.2 1957.8,332.2 1976,314 U10.2@1976,288.57
  TOP w10: R152.2@832.9,1071.5 R152.2@833.69,1071.5 936.5,1071.5 981,1027 v1(981,984)
  L3 w10: v1(981,984) 1136,984 1188.5,931.5 1437.5,931.5 1604.8,764.2 1892.18,764.2 2011,645.38 2011,586.37 2081,516.37 2081,277.6 1999.2,195.8 1942.8,195.8 1918.6,220 v1(1918,220)
  BOTTOM w4: v1(1918,220) 1918,-76.45 J8.4@1919.41,-77.86
XDSET_1_VBUS: R151.2 R154.2 R161.2 U10.6 | length 2858
  TOP w10: U10.6@1995.69,264.95 1995.69,247.31 2007,236 v1(2007,235)
  TOP w20: R154.2@796,916.31 796,917.1 851.9,917.1 882.8,948 v1(914,948)
  L3 w15: v1(914,948) 933.64,948 952.34,929.3 986.49,929.3 1050.49,865.3 1396.7,865.3 1599,663 1861,663 1982,542 2002,542 2053.7,490.3 2053.7,313.7 2007,267 v1(2007,235)
  L4 w15: v1(55,973.5) 188.5,973.5 214,948 v1(914,948) v1@915,948
  BOTTOM w10: R161.2@2000,85.5 1993,92.5 1993,188 2007.2,202.2 2007.2,234.8 v1(2007,235)
  BOTTOM w20: v1(55,973.5) 96.29,973.5 108.36,961.43 R151.2@108.75,961.04
XDSET_TCK: R70.2 U6.35 | length 1651.3
  TOP w4: v1(990,1526) 1035,1526 1042,1519 1072,1519 1091.33,1538.33 R70.2@1091.33,1538.73
  L3 w5: v1(282,1505.5) 401.6,1385.9 401.6,1303 494.6,1210 534,1210 644,1100 944.14,1100 999.7,1155.56 999.7,1230.3 892,1338 892,1528.9 905.1,1542 975,1542 990,1527 v1(990,1526)
  BOTTOM w4: v1(282,1505.5) 299.19,1522.69 U6.35@299.19,1551.19
XDSET_TDI: R30.2 U6.38 | length 1125.2
  TOP w4: R30.2@995.75,2116.73 995.75,2098.25 v1(1010,2084)
  L4 w5: v1(478.2,1948) 557.2,2027 953,2027 v1(1010,2084)
  BOTTOM w4: U6.38@346.44,1551.19 346.44,1587.68 340,1594.12 340,1692 320,1712 320,1802 370,1852 386,1852 406,1872 406,1902.8 451.2,1948 v1(478.2,1948)
XDSET_TDO: R71.2 U6.37 | length 1812.2
  TOP w4: v1(1018,1501) 1018,1500 1085.6,1500 R71.2@1124.33,1538.73
  L3 w5: v1(319,1606.5) 342.1,1606.5 418.4,1530.2 418.4,1303.2 501.6,1220 538.2,1220 645.3,1112.9 942.9,1112.9 989.7,1159.7 989.7,1226.16 882,1333.86 882,1533.04 903.96,1555 990.86,1555 1018,1527.86 v1(1018,1501)
  BOTTOM w4: v1(319,1606.5) 319,1593.3 330.69,1581.61 U6.37@330.69,1551.19
XDSET_TMS: R69.2 U6.36 | length 1651.1
  TOP w4: v1(959,1517) 969.8,1527.8 969.8,1536.8 981.2,1548.2 1031.53,1548.2 1041,1538.73 R69.2@1059.25,1538.73
  L3 w5: v1(321,1503.5) 293.9,1530.6 271.6,1530.6 256.9,1515.9 256.9,1485 383.5,1358.4 383.5,1305.3 488.8,1200 529.8,1200 639.8,1090 948.28,1090 1009.7,1151.42 1009.7,1234.44 950.94,1293.2 950.94,1362.81 959,1370.86 v1(959,1517)
  BOTTOM w4: U6.36@314.94,1551.19 314.94,1509.56 v1(321,1503.5)
pads on no net: D2.1@37.49,1105.47 D2.2@69.97,1105.47 FID1.1 FID2.1 FID3.1 FID4.1 FID5.1 FID6.1 J1.20 J1.22 J1.32 J1.34 J1.35 J1.37 J1.38 J1.39 J1.40 J1.41 J1.43 J1.45 J1.47 J1.49 J1.MH1 J1.MH2 J5.7 J5.20 J6.3 J6.11 J8.7 J8.8 LBL1.0 P6.MH1 SW1.1 SW1.3 SW2.1 SW2.3 U1. U4. U5.2 U5.4 U5.5 U5.6 U5.7 U5.9 U5.10 U5.11 U6.2 U6.3 U6.4 U6.5 U6.6 U6.11 U6.12 U6.13 U6.14 U6.15 U6.18 U6.19 U6.20 U6.21 U6.22 U6.23 U6.24 U6.27 U6.29 U6.30 U6.31 U6.32 U6.41 U6.42 U6.43 U6.44 U6.45 U6.46 U6.49 U6.50 U6.53 U6.54 U6.56 U6.57 U6.65 U6.67 U6.71 U6.72 U6.73 U6.74 U6.75 U6.76 U6.77 U6.78 U6.81 U6.82 U6.83 U6.84 U6.85 U6.86 U6.91 U6.92 U6.97 U6.98 U6.99 U6.100 U6.102 U6.103 U6.104 U6.105 U6.106 U6.107 U6.108 U6.109 U6.110 U6.111 U6.112 U6.116 U6.117 U6.118 U6.119 U6.120 U6.121 U6.123 U6.124 U6.125 U6.126 U6.127 U6.128 U7.3 U8.4A U8.4B U8.8A U8.8B U8.9A U8.9B U8.9C U8.9D U8.10A U8.10B U8.14A U8.14B U11.7 U11.9@436.9,1009.7 U11.9@436.9,1059.3 U14.9 U14.12

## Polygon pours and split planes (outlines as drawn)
no net on Top Solder (solid, pour order 766): 1740.13,1910.38 1792.23,1910.38 1792.23,1933.98 1740.13,1933.98 1740.13,1910.38
no net on Top Solder (solid): 1958.03,1860.38 2010.13,1860.38 2010.13,1883.98 1958.03,1883.98 1958.03,1860.38
no net on Top Solder (solid): 1740.13,1860.38 1792.23,1860.38 1792.23,1883.98 1740.13,1883.98 1740.13,1860.38
no net on Top Solder (solid): 1740.13,1960.38 1792.23,1960.38 1792.23,1983.98 1740.13,1983.98 1740.13,1960.38
no net on Top Solder (solid): 1740.13,2010.38 1792.23,2010.38 1792.23,2033.98 1740.13,2033.98 1740.13,2010.38
no net on Top Solder (solid): 1958.03,1910.38 2010.13,1910.38 2010.13,1933.98 1958.03,1933.98 1958.03,1910.38
no net on Top Solder (solid): 1958.03,1960.38 2010.13,1960.38 2010.13,1983.98 1958.03,1983.98 1958.03,1960.38
no net on Top Solder (solid): 1958.03,2010.38 2010.13,2010.38 2010.13,2033.98 1958.03,2033.98 1958.03,2010.38
no net on Top Solder (solid): 1974,2174.42 2001.92,2146.5 2358,2146.5 2358,2324.5 1596,2324.5 1596,2219.87 1974,2219.87
no net on Top Solder (solid): 76 vertices, not listed, extent 2191.21,590.27 3130.1,1748.3
no net on TOP "Top Layer-No Net" (solid, pour order 954): 2108.38,2181.95 2108.38,2187.85 2120.19,2187.85 2143.81,2188.44 2291.6,2188.44 2315.22,2187.85 2327.03,2187.85 2327.03,2181.95 2315.22,2181.95 2291.6,2181.36 2143.81,2181.36 2120.19,2181.95
no net on TOP "Top Layer-No Net" (solid, pour order 953): 1631.53,2270.05 1643.34,2270.05 1666.96,2269.46 2292.4,2269.46 2316.02,2270.05 2327.83,2270.05 2327.83,2275.95 2316.02,2275.95 2292.4,2276.54 1666.96,2276.54 1643.34,2275.95 1631.53,2275.95
GND on TOP "TOP-GND 1" (solid, remove dead copper, pour order 935): 2358,2324.5 2358,2146.5 1974,2146.5 1974,2219.5 1596,2219.5 1596,2324.5 2358,2324.5
NetC1_2 on TOP "TOP-UNNAMED_41_RESISTOR_I120_1" (solid, pour order 1008): 2010.13,2032.97 1958.03,2032.97 1958.03,2009.6 2010.13,2009.6
AR_VOUT_PA on TOP "TOP_AR_VOUT_PA_P929" (solid, remove dead copper, pour order 929): 28 vertices, not listed, extent 2435.66,1123.1 2537.04,1331.75
NetC79_1 on TOP "TOP_NETC79_1_P958" (solid, remove dead copper, pour order 958): 2153,165 2153,22 2159,16 2492,16 2512,36 2512,215 2499,228 2284,228 2238,182 2170,182
AR_1V8 on TOP "TOP_AR_1V8_P957" (solid, remove dead copper, pour order 957): 2169.48,1135.5 2176.41,1135.5 2179.6,1138.69 2179.6,1145.62 2179.6,1159.35 2161.35,1159.35 2089,1087 2073,1071 2073,1007 2110,970 2147,970 2173,996 2173,1076.69 2163,1086.69 2163,1129.02
GND on TOP "Top Layer-No Net" (solid, remove dead copper, pour order 952): 1807,2027.5 1807,1868 1942,1868 1942,2027.5
GND on TOP "TOP-GND 11" (solid, pour order 950): 146 vertices, not listed, extent 404.9,926.5 469.4,1143.5
GND on TOP "TOP-GND 10" (solid, remove dead copper, pour order 949): 247 vertices, not listed, extent 85,1255 374.65,1390
GND on TOP "TOP-GND 7" (solid, pour order 948): 162 vertices, not listed, extent 203.3,998.49 266.88,1020.8
GND on TOP "TOP-GND" (solid, pour order 947): 1792.23,1883.98 1740.13,1883.98 1740.13,1860.38 1792.23,1860.38 1792.23,1883.98
AR_QSPI_CS on TOP "TOP-AR_QSPI_CS" (solid, pour order 946): 1792.23,2033.98 1740.13,2033.98 1740.13,2010.38 1792.23,2010.38 1792.23,2033.98
NetR42_2 on TOP "TOP-UNNAMED_41_RESISTOR_I116_2" (solid, pour order 945): 1792.23,1933.98 1740.13,1933.98 1740.13,1910.38 1792.23,1910.38 1792.23,1933.98
NetR44_1 on TOP "TOP-UNNAMED_41_RESISTOR_I117_1" (solid, pour order 944): 2010.13,1933.98 1958.03,1933.98 1958.03,1910.38 2010.13,1910.38 2010.13,1933.98
NetR45_1 on TOP "TOP-UNNAMED_41_RESISTOR_I118_1" (solid, pour order 943): 2010.13,1883.98 1958.03,1883.98 1958.03,1860.38 2010.13,1860.38 2010.13,1883.98
NetR39_2 on TOP "TOP-UNNAMED_41_RESISTOR_I119_2" (solid, pour order 942): 1792.23,1983.98 1740.13,1983.98 1740.13,1960.38 1792.23,1960.38 1792.23,1983.98
NetR40_1 on TOP "TOP-UNNAMED_41_RESISTOR_I120_1" (solid, pour order 941): 2010.13,1983.98 1958.03,1983.98 1958.03,1960.38 2010.13,1960.38 2010.13,1983.98
NetC85_1 on TOP "TOP-UNNAMED_7_CAPNONPOLARIZED_I5_2" (solid, pour order 940): 194 vertices, not listed, extent 281.9,916.5 393.44,1055.5
RX1 on TOP "TOP-RX1" (solid, remove dead copper, pour order 928): 34 vertices, not listed, extent 2653.04,1586.07 2946.35,1645.13
RX2 on TOP "TOP-RX2" (solid, remove dead copper, pour order 927): 34 vertices, not listed, extent 2653.04,1511.27 2946.35,1570.32
RX3 on TOP "TOP-RX3" (solid, remove dead copper, pour order 926): 34 vertices, not listed, extent 2653.04,1436.47 2946.35,1495.52
RX4 on TOP "TOP-RX4" (solid, remove dead copper, pour order 925): 34 vertices, not listed, extent 2653.04,1361.66 2946.35,1420.72
TX1 on TOP "TOP-TX1" (solid, remove dead copper, pour order 924): 34 vertices, not listed, extent 2653.04,1155.37 2946.35,1214.43
TX2 on TOP "TOP-TX2" (solid, remove dead copper, pour order 923): 34 vertices, not listed, extent 2727.85,1005.77 3021.15,1064.82
TX3 on TOP "TOP-TX3" (solid, remove dead copper, pour order 922): 34 vertices, not listed, extent 2653.04,856.16 2946.35,915.21
VIN on TOP "TOP_VIN_P937" (solid, remove dead copper, pour order 937): 1481,2019 1485,2015 1553,2015 1568,2030 1568,2063 1613,2108 1613,2183 1598,2198 1491,2198 1481,2188
NetJ1_1 on TOP "TOP-UNNAMED_43_QSH03001XD_I1_1" (solid, pour order 933): 200 vertices, not listed, extent 1074.64,1728.5 1376.03,2133.5
AR_1V24 on TOP "TOP-PMIC_1V2" (solid, pour order 932): 2044,1702 2104,1642 2121,1642 2126,1637 2126,1625 2124,1623 2046,1623.01 2020,1649 1901,1649 1880.01,1670 1879.96,1731.1 1990.47,1731.09 2019.57,1702
AR_3V3 on TOP "TOP-+3.3VD" (solid, pour order 934): 46 vertices, not listed, extent 2199.7,1683.22 2279.99,1778.9
VIN on TOP "TOP_VIN_P959" (solid, remove dead copper, pour order 959): 2591,166.09 2591,35 2525,-31 2245,-31 2232,-44 2232,-154 2245,-167 2645,-167 2680,-132 2680,157.59 2657.14,180.44 2605.35,180.44
GND on TOP "TOP-GND 14" (solid, pour order 951): 29 vertices, not listed, extent 2470.96,1643.56 2511.09,1679.7
GND on TOP "Bottom Layer - L12-No Net" (solid, remove dead copper, pour order 930): 56 vertices, not listed, extent 2191.2,-223.91 3182.62,2386.89
GND on TOP "TOP-GND 3" (solid, pour order 938): 34 vertices, not listed, extent 2653.04,1660.87 2946.35,1719.93
GND on TOP "TOP-GND 4" (solid, remove dead copper, pour order 939): 34 vertices, not listed, extent 2653.04,1286.86 2946.35,1345.92
GND on TOP "TOP-GND 3" (solid, remove dead copper, pour order 955): 2398.5,1993 2697.5,1993 2697.5,2295 2398.5,2295 2398.5,1993
NetF1_2 on TOP "TOP_NETF1_2_P931" (solid, remove dead copper, pour order 931): 1052,53 1138,-33 1639,-33 1719,47 2093,47 2109,63 2109,177 2095,191 1757,191 1692,256 1122.76,256 1052,185.24
VIN on L4 "L4_VIN_P964" (solid, remove dead copper, pour order 964): 19 vertices, not listed, extent 647,-158 2608,830
GND on L4 "L4-GND" (solid, pour order 962): 555 vertices, not listed, extent 384.02,1961.83 938.88,2306.08
AR_1V8 on L4 "L4_AR_1V8_P966" (solid, remove dead copper, pour order 966): 2308,966 2450.65,966 2549,1064.35 2549,1598.99 2446,1702 2275,1702 2258,1685 2258,1562 2068,1372 2068,1072 2068,1025 2127,966
NetC85_1 on L4 "L4-UNNAMED_7_CAPNONPOLARIZED_I5_2" (solid, pour order 963): 96 vertices, not listed, extent 268.9,983.7 319.5,1073.6
GND on L4 "L4_GND_P961" (solid, remove dead copper, pour order 961): 2358,1406 2371.01,1393.01 2398,1393 2406,1385 2406,1352 2383,1329 2222,1329 2192,1359 2192,1484 2234.99,1526.99 2322,1527 2358,1491
VIN on L4 "L4_VIN_P960" (solid, remove dead copper, pour order 960): 19 vertices, not listed, extent 1308,682 1638,2197
3V3_REF on L4 "L4_3V3_REF_P965" (solid, remove dead copper, pour order 965): 1747,801 1747,479.78 1875.78,351 2739,351 2786,398 2786,719.01 2636,869 1815,869
GND on BOTTOM "BOTTOM-TPS_GND8" (solid, pour order 995): 1610,1357 1539,1357 1526,1344 1526,1315 1533,1308 1604,1308 1610,1302 1610,1198 1625,1183 1625,1100 1639,1086 1722,1086 1729,1093 1729,1306 1678,1357
GND on BOTTOM "BOTTOM_GND_P994" (solid, remove dead copper, pour order 994): 40 vertices, not listed, extent 1511,864 2530.5,1829
VCC_LDO_OUT on BOTTOM "BOTTOM_VCC_LDO_OUT_P979" (solid, remove dead copper, pour order 979): 27 vertices, not listed, extent 1283,1149 2705,2082
GND on BOTTOM "BOTTOM-RF2_DECOUP_GND" (solid, pour order 997): 2665,1335 2652,1322 2617,1322 2608,1313 2608,1293 2573,1258 2573,1220 2581,1212 2614,1212 2737,1335 2737,1401 2729,1409 2665,1409
GND on BOTTOM "BOTTOM-RF1_DECOUP_GND" (solid, pour order 996): 2578,1626 2578,1630 2591,1643 2645,1643 2645,1487 2631,1473 2559,1473 2544,1488 2544,1502 2571,1529 2571,1623 2591,1643 2591,1641 2579,1629
GND on BOTTOM "BOTTOM-PGND_B1" (solid, pour order 993): 21 vertices, not listed, extent 2007,734 2248,1019
GND on BOTTOM "BOTTOM-PGND_B0" (solid, pour order 992): 2272.84,758.95 2245.89,732 2216.14,732 2216,794 2223,801 2223,925 2274,925 2280,919 2280,856 2275,856 2273,854 2272.84,809
3V3 on BOTTOM "BOTTOM_3V3_P991" (solid, remove dead copper, pour order 991): 2767,685 2767,555 2758,546 2758,506 2764,500 2813,500 2818,495 2818,398 2803,383 2803,179 2807,175 2954,175 2954,628 2897,685
GND on BOTTOM "BOTTOM_GND_P990" (solid, remove dead copper, pour order 990): 96 vertices, not listed, extent 2152,-223.91 3182.03,2387.4
GND on BOTTOM "BOTTOM_GND_P989" (solid, remove dead copper, pour order 989): 2620,206.28 2622.72,206.28 2691,138 2752,138 2752,151 2721,182 2688,182 2688,240.36 2663.91,264.45 2663.91,269.29 2638.91,294.29 2570.91,294.29 2564.91,288.29 2564.91,219.29 2577.91,206.28
NetC18_2 on BOTTOM "BOTTOM_NETC18_2_P988" (solid, remove dead copper, pour order 988): 19 vertices, not listed, extent 2515,158 2751,374
VIN on BOTTOM "BOTTOM_VIN_P987" (solid, remove dead copper, pour order 987): 40 vertices, not listed, extent 2256,-152 2703.01,221
3V3_REF on BOTTOM "BOTTOM_3V3_REF_P986" (solid, remove dead copper, pour order 986): 1896,493 1884,505 1884,520 1876,528 1820,528 1812,520 1812,429 1986,429 1992,435 1992,470 1969.01,493
NetL4_2 on BOTTOM "BOTTOM_NETL4_2_P985" (solid, remove dead copper, pour order 985): 2024,536 2015,536 1988,509 1903,509 1894,518 1894,557 1903.99,566.99 2005,567 2043.69,567 2064.47,587.78 2087.22,587.78 2091,584 2091,573.76 2053.23,536
AR_1V8 on BOTTOM "BOTTOM_AR_1V8_P984" (solid, remove dead copper, pour order 984): 2493.01,1046 2168.01,1046 2135,1079 2101,1079 2095,1073 2095,996 2106,985 2112,979 2510,979 2510,1029
AR_1P0_RF2 on BOTTOM "BOTTOM_AR_1P0_RF2_P983" (solid, remove dead copper, pour order 983): 39 vertices, not listed, extent 2504,1230 2768,1847
AR_1P0_RF1 on BOTTOM "BOTTOM_AR_1P0_RF1_P982" (solid, remove dead copper, pour order 982): 25 vertices, not listed, extent 2308,1446 2560,1825
AR_VOUT_PA on BOTTOM "BOTTOM_AR_VOUT_PA_P981" (solid, remove dead copper, pour order 981): 2441,1214 2425,1198 2425,1141 2434,1132 2527,1132 2547,1152 2547,1194 2534,1207 2506,1207 2489,1224 2489,1275 2478,1286 2448,1286 2441,1279
1V24 on BOTTOM "BOTTOM_1V24_P978" (solid, remove dead copper, pour order 978): 34 vertices, not listed, extent 1453,768 1956,1480
1V8 on BOTTOM "BOTTOM_1V8_P977" (solid, remove dead copper, pour order 977): 2353,924 2343,914 2343,849 2343,776 2383,736 2475,736 2509,770 2509,903 2488.01,924
NetL2_1 on BOTTOM "BOTTOM_NETL2_1_P976" (solid, remove dead copper, pour order 976): 2254,723 2282.2,751.2 2282.2,846.2 2315.8,846.2 2326.5,835.5 2326.5,750.5 2270,694 2257,694 2254,697
NetL3_1 on BOTTOM "BOTTOM_NETL3_1_P975" (solid, remove dead copper, pour order 975): 2034,701 2042,693 2089,693 2089,705.52 2089,732 2039,782 2039,852 1990,852 1990,745 2026,709
3V3_REF on BOTTOM "BOTTOM_3V3_REF_P974" (solid, remove dead copper, pour order 974): 1753,745 1753,679 1776,656 2088,656 2091,659 2091,682 2087,686 2030,686 1960,756 1764,756
3V3_REF on BOTTOM "BOTTOM_3V3_REF_P973" (solid, remove dead copper, pour order 973): 17 vertices, not listed, extent 2254,573 2732,761
GND on BOTTOM "BOTTOM-GND 1" (solid, pour order 972): 2394.5,2082.99 2499.39,1977.22 2693.5,1991 2693.5,2293 2394.5,2293
AR_1V8 on BOTTOM "BOTTOM_AR_1V8_P971" (solid, remove dead copper, pour order 971): 20 vertices, not listed, extent 2424,1430.5 2533.01,1486
MCU_5V on BOTTOM "BOTTOM_MCU_5V_P970" (solid, remove dead copper, pour order 970): 471,787 471,503 513,461 576,461 593,478 592,479 592,593 672,673 672,778 663,787
GND on BOTTOM "BOTTOM_GND_P969" (solid, remove dead copper, pour order 969): 1366,1131 1432,1131 1438,1125 1438,948 1402,948 1250,1100 1250,1260 1256,1266 1336.01,1266 1342,1260 1342,1154.99
GND on BOTTOM "BOTTOM-AGND" (solid, pour order 968): 2543,61 2543,67 2527,67 2527,51 2514,38 2514,9 2496,-9 2413,-9 2413,-58 2497,-58 2543,-12
NetC32_1 on BOTTOM "BOTTOM_NETC32_1_P967" (solid, remove dead copper, pour order 967): 2476,107 2476,8 2468,0 2415,0 2395,20 2395,94 2410,109 2474,109
AR_1V24 on BOTTOM "BOTTOM_AR_1V24_P980" (solid, remove dead copper, pour order 980): 31 vertices, not listed, extent 1723,1440 2390,1794
GND on L3 "L3-GND 4" (solid, pour order 1000): 147 vertices, not listed, extent 128.34,1301 365.98,1529.24
GND on L3 "L3-GND" (solid, pour order 999): 2405,2275 2675,2275 2675,2020 2495,2020 2405,2110 2405,2275
VIN on L3 "L3_VIN_P998" (solid, remove dead copper, pour order 998): 1342,810 1374.01,777.99 1374,691 1345,662 1136.8,662 1103.8,629 795,629 772,652 772,795 796,819 950,819 959,810
GND on L3 "L3_GND_P1001" (solid, remove dead copper, pour order 1001): 3156.74,-243.26 -87.75,-243.25 -116,-214.99 -116,2367 -75,2408 3157,2408 3199.26,2365.74 3199.26,-200.74
GND on L2 "L2-GND 1" (solid, pour order 1003): 2424.5,367 2424.5,120 2669.5,120 2669.5,367 2424.5,367
GND on L2 "L2-GND" (solid, pour order 1002): 2422,2264.5 2422,2017.5 2667,2017.5 2667,2264.5 2422,2264.5
GND on L2 "L2_GND_P1004" (solid, remove dead copper, pour order 1004): 3156.74,-243.26 -87.75,-243.25 -116,-214.99 -116,2367 -75,2408 3157,2408 3199.26,2365.74 3199.26,-200.74
no net on M6 Assembly Bottom (solid): 3048.2,1870.7 ccw(c3006.2,1870.7) 3006.2,1912.7 ccw(c3006.2,1870.7) 2964.2,1870.7 ccw(c3006.2,1870.7) 3006.2,1828.7 ccw(c3006.2,1870.7) 3048.2,1870.7
no net on M6 Assembly Bottom (solid): 238,-40.5 ccw(c196,-40.5) 196,1.5 ccw(c196,-40.5) 154,-40.5 ccw(c196,-40.5) 196,-82.5 ccw(c196,-40.5) 238,-40.5
no net on M6 Assembly Bottom (solid): 238,2287.5 ccw(c196,2287.5) 196,2329.5 ccw(c196,2287.5) 154,2287.5 ccw(c196,2287.5) 196,2245.5 ccw(c196,2287.5) 238,2287.5
no net on M5 Assembly Top (solid): 238,2287.5 ccw(c196,2287.5) 196,2329.5 ccw(c196,2287.5) 154,2287.5 ccw(c196,2287.5) 196,2245.5 ccw(c196,2287.5) 238,2287.5
no net on M5 Assembly Top (solid): 3048.2,1870.7 ccw(c3006.2,1870.7) 3006.2,1912.7 ccw(c3006.2,1870.7) 2964.2,1870.7 ccw(c3006.2,1870.7) 3006.2,1828.7 ccw(c3006.2,1870.7) 3048.2,1870.7
no net on M5 Assembly Top (solid): 238,-40.5 ccw(c196,-40.5) 196,1.5 ccw(c196,-40.5) 154,-40.5 ccw(c196,-40.5) 196,-82.5 ccw(c196,-40.5) 238,-40.5
GND on L5 "L5_GND_P1006" (solid, remove dead copper, pour order 1006): 3156.74,-243.26 -87.75,-243.25 -116,-214.99 -116,2367 -75,2408 3157,2408 3199.26,2365.74 3199.26,-200.74

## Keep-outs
TOP:
  circle w10: c3033.56,2240 r92.09
  circle w10: c3033.56,0 r92.09
L2:
  circle w10: c1209.9,1781.14 r44.95
  circle w10: c417.38,1781.14 r44.95
  circle w10: c3033.56,0 r92.09
  circle w10: c3033.56,2240 r92.09
L3:
  circle w10: c3033.56,2240 r92.09
  circle w10: c3033.56,0 r92.09
L4:
  circle w10: c1209.9,1781.14 r44.95
  circle w10: c3033.56,0 r92.09
  circle w10: c3033.56,2240 r92.09
L5:
  circle w10: c1209.9,1781.14 r44.95
  circle w10: c417.38,1781.14 r44.95
  circle w10: c3033.56,2240 r92.09
  circle w10: c3033.56,0 r92.09
BOTTOM:
  circle w10: c3033.56,2240 r92.09
  circle w10: c3033.56,0 r92.09
Keep-Out Layer:
  lines w4: -102.75,-171.24 ccw(c-32.75,-171.24) -32.75,-241.24 3127.25,-241.24 ccw(c3127.25,-171.24) 3197.25,-171.24 3197.25,2332.5 ccw(c3127.25,2332.5) 3127.25,2402.5 -32.75,2402.5 ccw(c-32.75,2332.5) -102.75,2332.5 -102.75,-171.24
  text ".Layer_Name" at 269,-1200.49 h60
